VERSION 5.7 ;
  NOWIREEXTENSIONATPIN ON ;
  DIVIDERCHAR "/" ;
  BUSBITCHARS "[]" ;
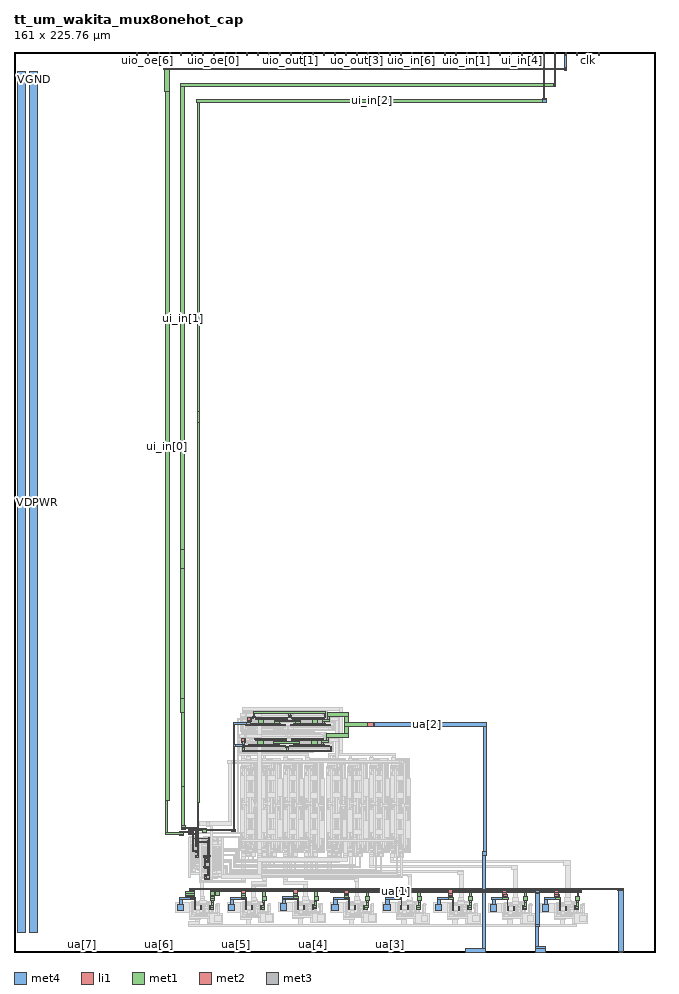
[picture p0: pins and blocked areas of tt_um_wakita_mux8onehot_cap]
MACRO tt_um_wakita_mux8onehot_cap
  CLASS BLOCK ;
  FOREIGN tt_um_wakita_mux8onehot_cap ;
  ORIGIN 0.000 0.000 ;
  SIZE 161.000 BY 225.760 ;
  PIN clk
    DIRECTION INPUT ;
    USE SIGNAL ;
    PORT
      LAYER met4 ;
        RECT 143.830 224.760 144.130 225.760 ;
    END
  END clk
  PIN ena
    DIRECTION INPUT ;
    USE SIGNAL ;
    PORT
      LAYER met4 ;
        RECT 146.590 224.760 146.890 225.760 ;
    END
  END ena
  PIN rst_n
    DIRECTION INPUT ;
    USE SIGNAL ;
    PORT
      LAYER met4 ;
        RECT 141.070 224.760 141.370 225.760 ;
    END
  END rst_n
  PIN ua[0]
    DIRECTION INOUT ;
    USE SIGNAL ;
    ANTENNAGATEAREA 8.000000 ;
    PORT
      LAYER li1 ;
        RECT 45.270 10.600 45.440 11.600 ;
        RECT 46.820 10.600 46.990 11.600 ;
        RECT 58.120 10.620 58.290 11.620 ;
        RECT 59.670 10.620 59.840 11.620 ;
        RECT 71.130 10.690 71.300 11.690 ;
        RECT 72.680 10.690 72.850 11.690 ;
        RECT 83.980 10.620 84.150 11.620 ;
        RECT 85.530 10.620 85.700 11.620 ;
        RECT 97.100 10.570 97.270 11.570 ;
        RECT 98.650 10.570 98.820 11.570 ;
        RECT 110.000 10.520 110.170 11.520 ;
        RECT 111.550 10.520 111.720 11.520 ;
        RECT 123.740 10.480 123.910 11.480 ;
        RECT 125.290 10.480 125.460 11.480 ;
        RECT 136.830 10.480 137.000 11.480 ;
        RECT 138.380 10.480 138.550 11.480 ;
      LAYER met1 ;
        RECT 44.120 15.280 45.120 15.450 ;
        RECT 42.930 15.120 45.120 15.280 ;
        RECT 42.930 14.560 45.200 15.120 ;
        RECT 42.930 14.090 45.230 14.560 ;
        RECT 57.000 14.190 58.100 14.640 ;
        RECT 70.020 14.290 71.120 14.740 ;
        RECT 82.790 14.390 83.890 14.650 ;
        RECT 42.930 13.920 45.190 14.090 ;
        RECT 44.190 13.710 45.190 13.920 ;
        RECT 57.040 13.730 58.040 14.190 ;
        RECT 70.050 13.800 71.050 14.290 ;
        RECT 82.790 14.200 83.900 14.390 ;
        RECT 44.190 13.370 45.460 13.710 ;
        RECT 57.040 13.390 58.310 13.730 ;
        RECT 70.050 13.460 71.320 13.800 ;
        RECT 44.510 13.220 45.460 13.370 ;
        RECT 57.360 13.240 58.310 13.390 ;
        RECT 70.370 13.310 71.320 13.460 ;
        RECT 82.900 13.730 83.900 14.200 ;
        RECT 95.950 14.140 97.050 14.590 ;
        RECT 82.900 13.390 84.170 13.730 ;
        RECT 45.280 11.580 45.420 13.220 ;
        RECT 58.130 11.600 58.270 13.240 ;
        RECT 71.140 11.670 71.280 13.310 ;
        RECT 83.220 13.240 84.170 13.390 ;
        RECT 96.020 13.680 97.020 14.140 ;
        RECT 108.890 14.050 109.990 14.500 ;
        RECT 96.020 13.340 97.290 13.680 ;
        RECT 45.240 10.620 45.470 11.580 ;
        RECT 46.790 10.620 47.020 11.580 ;
        RECT 58.090 10.640 58.320 11.600 ;
        RECT 59.640 10.640 59.870 11.600 ;
        RECT 71.100 10.710 71.330 11.670 ;
        RECT 72.650 10.710 72.880 11.670 ;
        RECT 83.990 11.600 84.130 13.240 ;
        RECT 96.340 13.190 97.290 13.340 ;
        RECT 108.920 13.630 109.920 14.050 ;
        RECT 122.620 14.040 123.720 14.490 ;
        RECT 135.650 14.040 136.750 14.490 ;
        RECT 108.920 13.290 110.190 13.630 ;
        RECT 83.950 10.640 84.180 11.600 ;
        RECT 85.500 10.640 85.730 11.600 ;
        RECT 97.110 11.550 97.250 13.190 ;
        RECT 109.240 13.140 110.190 13.290 ;
        RECT 122.660 13.590 123.660 14.040 ;
        RECT 135.750 13.590 136.750 14.040 ;
        RECT 122.660 13.250 123.930 13.590 ;
        RECT 135.750 13.250 137.020 13.590 ;
        RECT 97.070 10.590 97.300 11.550 ;
        RECT 98.620 10.590 98.850 11.550 ;
        RECT 110.010 11.500 110.150 13.140 ;
        RECT 122.980 13.100 123.930 13.250 ;
        RECT 136.070 13.100 137.020 13.250 ;
        RECT 109.970 10.540 110.200 11.500 ;
        RECT 111.520 10.540 111.750 11.500 ;
        RECT 123.750 11.460 123.890 13.100 ;
        RECT 136.840 11.460 136.980 13.100 ;
        RECT 123.710 10.500 123.940 11.460 ;
        RECT 125.260 10.500 125.490 11.460 ;
        RECT 136.800 10.500 137.030 11.460 ;
        RECT 138.350 10.500 138.580 11.460 ;
      LAYER met2 ;
        RECT 44.160 15.920 45.180 15.930 ;
        RECT 44.120 15.890 65.770 15.920 ;
        RECT 70.070 15.890 71.040 15.950 ;
        RECT 151.510 15.910 152.780 15.970 ;
        RECT 86.560 15.890 108.210 15.900 ;
        RECT 138.420 15.890 152.780 15.910 ;
        RECT 44.120 15.650 152.780 15.890 ;
        RECT 44.160 13.900 45.180 15.650 ;
        RECT 57.080 14.690 58.050 15.650 ;
        RECT 65.380 15.640 152.780 15.650 ;
        RECT 65.380 15.630 139.680 15.640 ;
        RECT 65.380 15.620 87.030 15.630 ;
        RECT 57.050 14.140 58.050 14.690 ;
        RECT 70.070 14.790 71.040 15.620 ;
        RECT 70.070 14.240 71.070 14.790 ;
        RECT 82.880 14.700 83.850 15.620 ;
        RECT 82.840 14.450 83.850 14.700 ;
        RECT 95.990 14.640 96.960 15.630 ;
        RECT 107.780 15.620 129.430 15.630 ;
        RECT 82.840 14.150 83.840 14.450 ;
        RECT 95.990 14.420 97.000 14.640 ;
        RECT 96.000 14.090 97.000 14.420 ;
        RECT 108.930 14.550 109.900 15.620 ;
        RECT 108.930 14.230 109.940 14.550 ;
        RECT 122.660 14.540 123.630 15.620 ;
        RECT 135.670 14.540 136.640 15.630 ;
        RECT 151.510 15.340 152.780 15.640 ;
        RECT 122.660 14.370 123.670 14.540 ;
        RECT 135.670 14.370 136.700 14.540 ;
        RECT 108.940 14.000 109.940 14.230 ;
        RECT 122.670 13.990 123.670 14.370 ;
        RECT 135.700 13.990 136.700 14.370 ;
        RECT 44.560 13.170 45.410 13.760 ;
        RECT 57.410 13.190 58.260 13.780 ;
        RECT 70.420 13.260 71.270 13.850 ;
        RECT 83.270 13.190 84.120 13.780 ;
        RECT 96.390 13.140 97.240 13.730 ;
        RECT 109.290 13.090 110.140 13.680 ;
        RECT 123.030 13.050 123.880 13.640 ;
        RECT 136.120 13.050 136.970 13.640 ;
      LAYER met3 ;
        RECT 151.460 15.365 152.830 15.945 ;
        RECT 44.510 13.195 45.460 13.735 ;
        RECT 57.360 13.215 58.310 13.755 ;
        RECT 70.370 13.285 71.320 13.825 ;
        RECT 83.220 13.215 84.170 13.755 ;
        RECT 96.340 13.165 97.290 13.705 ;
        RECT 109.240 13.115 110.190 13.655 ;
        RECT 122.980 13.075 123.930 13.615 ;
        RECT 136.070 13.075 137.020 13.615 ;
      LAYER met4 ;
        RECT 151.505 15.900 152.785 15.925 ;
        RECT 151.505 15.385 152.800 15.900 ;
        RECT 70.415 13.800 71.275 13.805 ;
        RECT 57.405 13.730 58.265 13.735 ;
        RECT 44.555 13.710 45.415 13.715 ;
        RECT 41.400 13.215 45.415 13.710 ;
        RECT 54.250 13.235 58.265 13.730 ;
        RECT 67.260 13.305 71.275 13.800 ;
        RECT 83.265 13.730 84.125 13.735 ;
        RECT 67.260 13.270 71.240 13.305 ;
        RECT 41.400 13.180 45.380 13.215 ;
        RECT 54.250 13.200 58.230 13.235 ;
        RECT 41.440 12.005 42.320 13.180 ;
        RECT 54.290 12.025 55.170 13.200 ;
        RECT 67.300 12.095 68.180 13.270 ;
        RECT 80.110 13.235 84.125 13.730 ;
        RECT 96.385 13.680 97.245 13.685 ;
        RECT 80.110 13.200 84.090 13.235 ;
        RECT 40.975 10.395 42.585 12.005 ;
        RECT 53.825 10.415 55.435 12.025 ;
        RECT 66.835 10.485 68.445 12.095 ;
        RECT 80.150 12.025 81.030 13.200 ;
        RECT 93.230 13.185 97.245 13.680 ;
        RECT 109.285 13.630 110.145 13.635 ;
        RECT 93.230 13.150 97.210 13.185 ;
        RECT 79.685 10.415 81.295 12.025 ;
        RECT 93.270 11.975 94.150 13.150 ;
        RECT 106.130 13.135 110.145 13.630 ;
        RECT 123.025 13.590 123.885 13.595 ;
        RECT 136.115 13.590 136.975 13.595 ;
        RECT 106.130 13.100 110.110 13.135 ;
        RECT 92.805 10.365 94.415 11.975 ;
        RECT 106.170 11.925 107.050 13.100 ;
        RECT 119.870 13.095 123.885 13.590 ;
        RECT 132.960 13.095 136.975 13.590 ;
        RECT 119.870 13.060 123.850 13.095 ;
        RECT 132.960 13.060 136.940 13.095 ;
        RECT 105.705 10.315 107.315 11.925 ;
        RECT 119.910 11.885 120.790 13.060 ;
        RECT 133.000 11.885 133.880 13.060 ;
        RECT 119.445 10.275 121.055 11.885 ;
        RECT 132.535 10.275 134.145 11.885 ;
        RECT 151.620 0.200 152.800 15.385 ;
        RECT 151.810 0.000 152.710 0.200 ;
    END
  END ua[0]
  PIN ua[1]
    DIRECTION INOUT ;
    USE SIGNAL ;
    ANTENNADIFFAREA 2.320000 ;
    PORT
      LAYER li1 ;
        RECT 49.040 10.660 49.210 11.700 ;
        RECT 61.890 10.680 62.060 11.720 ;
        RECT 74.900 10.750 75.070 11.790 ;
        RECT 87.750 10.680 87.920 11.720 ;
        RECT 100.870 10.630 101.040 11.670 ;
        RECT 113.770 10.580 113.940 11.620 ;
        RECT 127.510 10.540 127.680 11.580 ;
        RECT 140.600 10.540 140.770 11.580 ;
      LAYER met1 ;
        RECT 49.380 15.340 50.360 15.370 ;
        RECT 49.380 15.320 63.180 15.340 ;
        RECT 79.430 15.320 97.290 15.340 ;
        RECT 130.790 15.330 131.720 15.350 ;
        RECT 114.490 15.320 142.240 15.330 ;
        RECT 49.380 15.130 142.240 15.320 ;
        RECT 49.370 15.090 142.240 15.130 ;
        RECT 49.370 14.130 50.370 15.090 ;
        RECT 50.580 14.240 51.580 15.090 ;
        RECT 62.440 15.070 142.240 15.090 ;
        RECT 49.380 13.950 50.360 14.130 ;
        RECT 62.440 13.970 63.050 15.070 ;
        RECT 75.440 14.040 76.050 15.070 ;
        RECT 79.430 15.050 142.240 15.070 ;
        RECT 49.380 13.430 50.400 13.950 ;
        RECT 49.400 12.950 50.400 13.430 ;
        RECT 62.250 12.970 63.250 13.970 ;
        RECT 75.260 13.040 76.260 14.040 ;
        RECT 88.320 13.970 88.930 15.050 ;
        RECT 49.590 12.460 50.090 12.950 ;
        RECT 62.440 12.480 62.940 12.970 ;
        RECT 75.450 12.550 75.950 13.040 ;
        RECT 88.110 12.970 89.110 13.970 ;
        RECT 101.300 13.920 101.910 15.050 ;
        RECT 114.240 15.030 142.240 15.050 ;
        RECT 49.010 11.620 49.240 11.680 ;
        RECT 49.620 11.620 50.090 12.460 ;
        RECT 49.010 11.130 50.090 11.620 ;
        RECT 61.860 11.640 62.090 11.700 ;
        RECT 62.470 11.640 62.940 12.480 ;
        RECT 61.860 11.150 62.940 11.640 ;
        RECT 74.870 11.710 75.100 11.770 ;
        RECT 75.480 11.710 75.950 12.550 ;
        RECT 88.300 12.480 88.800 12.970 ;
        RECT 101.230 12.920 102.230 13.920 ;
        RECT 114.240 13.870 114.850 15.030 ;
        RECT 74.870 11.220 75.950 11.710 ;
        RECT 87.720 11.640 87.950 11.700 ;
        RECT 88.330 11.640 88.800 12.480 ;
        RECT 101.420 12.430 101.920 12.920 ;
        RECT 114.130 12.870 115.130 13.870 ;
        RECT 127.980 13.830 128.590 15.030 ;
        RECT 141.270 13.830 141.690 15.030 ;
        RECT 49.010 10.760 50.070 11.130 ;
        RECT 61.860 10.780 62.920 11.150 ;
        RECT 74.870 10.850 75.930 11.220 ;
        RECT 87.720 11.150 88.800 11.640 ;
        RECT 100.840 11.590 101.070 11.650 ;
        RECT 101.450 11.590 101.920 12.430 ;
        RECT 114.320 12.380 114.820 12.870 ;
        RECT 127.870 12.830 128.870 13.830 ;
        RECT 140.960 12.830 141.960 13.830 ;
        RECT 49.010 10.680 49.240 10.760 ;
        RECT 61.860 10.700 62.090 10.780 ;
        RECT 74.870 10.770 75.100 10.850 ;
        RECT 87.720 10.780 88.780 11.150 ;
        RECT 100.840 11.100 101.920 11.590 ;
        RECT 113.740 11.540 113.970 11.600 ;
        RECT 114.350 11.540 114.820 12.380 ;
        RECT 128.060 12.340 128.560 12.830 ;
        RECT 141.150 12.340 141.650 12.830 ;
        RECT 87.720 10.700 87.950 10.780 ;
        RECT 100.840 10.730 101.900 11.100 ;
        RECT 113.740 11.050 114.820 11.540 ;
        RECT 127.480 11.500 127.710 11.560 ;
        RECT 128.090 11.500 128.560 12.340 ;
        RECT 100.840 10.650 101.070 10.730 ;
        RECT 113.740 10.680 114.800 11.050 ;
        RECT 127.480 11.010 128.560 11.500 ;
        RECT 140.570 11.500 140.800 11.560 ;
        RECT 141.180 11.500 141.650 12.340 ;
        RECT 140.570 11.010 141.650 11.500 ;
        RECT 113.740 10.600 113.970 10.680 ;
        RECT 127.480 10.640 128.540 11.010 ;
        RECT 140.570 10.640 141.630 11.010 ;
        RECT 127.480 10.560 127.710 10.640 ;
        RECT 140.570 10.560 140.800 10.640 ;
      LAYER met2 ;
        RECT 130.840 14.980 131.670 15.400 ;
      LAYER met3 ;
        RECT 130.790 15.005 131.720 15.375 ;
      LAYER met4 ;
        RECT 130.840 15.355 131.700 15.380 ;
        RECT 130.835 15.025 131.700 15.355 ;
        RECT 130.840 14.760 131.700 15.025 ;
        RECT 130.910 6.800 131.700 14.760 ;
        RECT 130.890 6.510 131.700 6.800 ;
        RECT 130.890 1.380 131.690 6.510 ;
        RECT 130.880 1.000 133.380 1.380 ;
        RECT 130.880 0.000 133.390 1.000 ;
        RECT 130.880 -0.030 133.380 0.000 ;
    END
  END ua[1]
  PIN ua[2]
    DIRECTION INOUT ;
    USE SIGNAL ;
    ANTENNADIFFAREA 20.879999 ;
    PORT
      LAYER li1 ;
        RECT 60.595 58.615 68.635 58.785 ;
        RECT 69.685 58.615 77.725 58.785 ;
        RECT 58.130 56.935 68.170 57.105 ;
        RECT 69.310 56.935 79.350 57.105 ;
        RECT 60.405 53.325 68.445 53.495 ;
        RECT 69.495 53.325 77.535 53.495 ;
        RECT 57.940 51.645 67.980 51.815 ;
        RECT 69.120 51.645 79.160 51.815 ;
      LAYER met1 ;
        RECT 78.855 60.125 83.915 60.175 ;
        RECT 78.665 59.175 83.915 60.125 ;
        RECT 78.665 59.125 79.925 59.175 ;
        RECT 60.615 58.585 68.615 58.815 ;
        RECT 69.705 58.665 77.705 58.815 ;
        RECT 69.705 58.585 77.945 58.665 ;
        RECT 60.695 58.315 68.605 58.585 ;
        RECT 69.755 58.385 77.945 58.585 ;
        RECT 78.665 58.385 79.195 59.125 ;
        RECT 61.385 57.405 62.685 58.315 ;
        RECT 65.315 58.105 66.615 58.315 ;
        RECT 69.755 58.305 79.195 58.385 ;
        RECT 70.575 58.105 71.875 58.305 ;
        RECT 65.315 57.695 71.875 58.105 ;
        RECT 65.315 57.405 66.615 57.695 ;
        RECT 58.965 57.135 66.875 57.405 ;
        RECT 70.575 57.375 71.875 57.695 ;
        RECT 74.915 57.375 76.215 58.305 ;
        RECT 77.365 57.915 79.195 58.305 ;
        RECT 77.365 57.375 77.945 57.915 ;
        RECT 82.915 57.580 83.915 59.175 ;
        RECT 85.400 57.590 90.120 57.610 ;
        RECT 85.280 57.580 90.120 57.590 ;
        RECT 70.225 57.135 78.135 57.375 ;
        RECT 58.150 56.905 68.150 57.135 ;
        RECT 69.330 56.905 79.330 57.135 ;
        RECT 82.915 56.600 90.120 57.580 ;
        RECT 82.915 54.835 83.915 56.600 ;
        RECT 85.280 56.590 86.280 56.600 ;
        RECT 78.475 53.835 83.915 54.835 ;
        RECT 60.425 53.295 68.425 53.525 ;
        RECT 69.515 53.375 77.515 53.525 ;
        RECT 69.515 53.295 77.755 53.375 ;
        RECT 60.505 53.025 68.415 53.295 ;
        RECT 69.565 53.095 77.755 53.295 ;
        RECT 78.475 53.095 79.005 53.835 ;
        RECT 61.195 52.115 62.495 53.025 ;
        RECT 65.125 52.815 66.425 53.025 ;
        RECT 69.565 53.015 79.005 53.095 ;
        RECT 70.385 52.815 71.685 53.015 ;
        RECT 65.125 52.405 71.685 52.815 ;
        RECT 65.125 52.115 66.425 52.405 ;
        RECT 58.775 51.845 66.685 52.115 ;
        RECT 70.385 52.085 71.685 52.405 ;
        RECT 74.725 52.085 76.025 53.015 ;
        RECT 77.175 52.625 79.005 53.015 ;
        RECT 77.175 52.085 77.755 52.625 ;
        RECT 70.035 51.845 77.945 52.085 ;
        RECT 57.960 51.615 67.960 51.845 ;
        RECT 69.140 51.615 79.140 51.845 ;
      LAYER met2 ;
        RECT 88.780 56.600 90.060 57.640 ;
      LAYER met3 ;
        RECT 88.730 57.570 90.110 57.615 ;
        RECT 88.610 56.650 90.370 57.570 ;
        RECT 88.730 56.625 90.110 56.650 ;
      LAYER met4 ;
        RECT 88.730 57.575 118.340 57.610 ;
        RECT 88.655 57.460 118.340 57.575 ;
        RECT 88.655 56.645 118.400 57.460 ;
        RECT 88.730 56.600 118.400 56.645 ;
        RECT 117.680 25.230 118.400 56.600 ;
        RECT 117.560 24.260 118.400 25.230 ;
        RECT 113.170 0.950 114.070 1.000 ;
        RECT 117.560 0.950 118.380 24.260 ;
        RECT 113.170 0.000 118.380 0.950 ;
        RECT 113.360 -0.010 118.380 0.000 ;
    END
  END ua[2]
  PIN ua[3]
    DIRECTION INOUT ;
    USE SIGNAL ;
    PORT
      LAYER met4 ;
        RECT 93.850 0.000 94.750 1.000 ;
    END
  END ua[3]
  PIN ua[4]
    DIRECTION INOUT ;
    USE SIGNAL ;
    PORT
      LAYER met4 ;
        RECT 74.530 0.000 75.430 1.000 ;
    END
  END ua[4]
  PIN ua[5]
    DIRECTION INOUT ;
    USE SIGNAL ;
    PORT
      LAYER met4 ;
        RECT 55.210 0.000 56.110 1.000 ;
    END
  END ua[5]
  PIN ua[6]
    DIRECTION INOUT ;
    USE SIGNAL ;
    PORT
      LAYER met4 ;
        RECT 35.890 0.000 36.790 1.000 ;
    END
  END ua[6]
  PIN ua[7]
    DIRECTION INOUT ;
    USE SIGNAL ;
    PORT
      LAYER met4 ;
        RECT 16.570 0.000 17.470 1.000 ;
    END
  END ua[7]
  PIN ui_in[0]
    DIRECTION INPUT ;
    USE SIGNAL ;
    ANTENNAGATEAREA 0.873000 ;
    PORT
      LAYER li1 ;
        RECT 45.500 25.120 45.750 25.450 ;
        RECT 47.590 23.860 48.440 24.160 ;
        RECT 48.470 22.435 48.780 23.130 ;
        RECT 47.900 18.915 48.150 18.970 ;
        RECT 47.900 18.560 48.225 18.915 ;
        RECT 47.900 18.295 48.510 18.560 ;
      LAYER met1 ;
        RECT 138.160 221.670 138.610 221.750 ;
        RECT 37.510 221.250 138.610 221.670 ;
        RECT 37.750 215.770 39.000 221.250 ;
        RECT 138.160 221.190 138.610 221.250 ;
        RECT 37.950 38.080 38.980 215.770 ;
        RECT 38.010 29.940 38.530 38.080 ;
        RECT 41.500 30.210 42.500 30.280 ;
        RECT 41.500 29.940 45.145 30.210 ;
        RECT 38.010 29.880 45.145 29.940 ;
        RECT 38.010 29.540 42.500 29.880 ;
        RECT 41.500 29.280 42.500 29.540 ;
        RECT 44.815 28.395 45.145 29.880 ;
        RECT 44.805 28.045 45.145 28.395 ;
        RECT 48.835 28.555 49.105 28.645 ;
        RECT 48.835 28.265 49.115 28.555 ;
        RECT 44.815 25.460 45.145 28.045 ;
        RECT 45.475 25.460 45.775 25.505 ;
        RECT 44.815 25.130 45.775 25.460 ;
        RECT 45.475 25.075 45.775 25.130 ;
        RECT 47.525 24.165 48.225 24.185 ;
        RECT 47.525 23.845 48.265 24.165 ;
        RECT 48.945 24.155 49.115 28.265 ;
        RECT 47.525 23.825 48.225 23.845 ;
        RECT 48.900 23.835 49.160 24.155 ;
        RECT 48.475 23.105 48.755 23.125 ;
        RECT 48.455 22.995 48.755 23.105 ;
        RECT 48.355 22.925 48.755 22.995 ;
        RECT 48.945 22.925 49.115 23.835 ;
        RECT 48.355 22.615 49.160 22.925 ;
        RECT 48.355 22.555 48.755 22.615 ;
        RECT 48.900 22.605 49.160 22.615 ;
        RECT 48.455 22.445 48.755 22.555 ;
        RECT 48.475 22.435 48.755 22.445 ;
        RECT 47.910 18.975 48.160 18.980 ;
        RECT 47.875 18.560 48.255 18.975 ;
        RECT 48.945 18.560 49.115 22.605 ;
        RECT 47.875 18.350 49.115 18.560 ;
        RECT 47.875 18.310 49.040 18.350 ;
        RECT 47.875 18.245 48.255 18.310 ;
      LAYER met2 ;
        RECT 138.210 221.140 138.560 221.800 ;
        RECT 43.970 30.210 44.300 30.240 ;
        RECT 43.660 29.880 44.300 30.210 ;
        RECT 43.970 29.850 44.300 29.880 ;
        RECT 44.815 28.565 45.135 28.600 ;
        RECT 48.785 28.565 49.155 28.595 ;
        RECT 44.815 28.370 49.155 28.565 ;
        RECT 44.815 28.340 45.135 28.370 ;
        RECT 48.785 28.315 49.155 28.370 ;
        RECT 47.495 24.080 47.815 24.125 ;
        RECT 48.870 24.080 49.190 24.125 ;
        RECT 47.495 23.910 49.190 24.080 ;
        RECT 47.495 23.865 47.815 23.910 ;
        RECT 48.870 23.865 49.190 23.910 ;
      LAYER met3 ;
        RECT 138.160 221.165 138.610 221.775 ;
      LAYER met4 ;
        RECT 138.310 225.170 138.610 225.760 ;
        RECT 138.210 224.760 138.610 225.170 ;
        RECT 138.210 221.755 138.540 224.760 ;
        RECT 138.205 221.185 138.565 221.755 ;
    END
  END ui_in[0]
  PIN ui_in[1]
    DIRECTION INPUT ;
    USE SIGNAL ;
    ANTENNAGATEAREA 0.873000 ;
    PORT
      LAYER li1 ;
        RECT 45.515 26.830 45.735 26.835 ;
        RECT 45.500 26.500 45.750 26.830 ;
        RECT 48.470 25.195 48.780 25.890 ;
        RECT 47.590 21.100 48.440 21.400 ;
        RECT 47.900 19.190 48.150 19.530 ;
      LAYER met1 ;
        RECT 41.870 217.800 42.790 217.950 ;
        RECT 135.480 217.800 135.870 217.810 ;
        RECT 41.740 217.130 135.870 217.800 ;
        RECT 41.870 100.850 42.790 217.130 ;
        RECT 41.840 96.160 42.790 100.850 ;
        RECT 41.840 63.550 42.750 96.160 ;
        RECT 41.840 60.070 42.830 63.550 ;
        RECT 41.910 41.410 42.830 60.070 ;
        RECT 41.960 31.660 42.800 41.410 ;
        RECT 41.920 31.320 42.920 31.660 ;
        RECT 41.920 30.940 45.840 31.320 ;
        RECT 41.920 30.660 42.920 30.940 ;
        RECT 45.480 29.730 45.820 30.940 ;
        RECT 45.465 29.580 45.820 29.730 ;
        RECT 45.465 26.475 45.795 29.580 ;
        RECT 48.475 27.375 48.795 27.875 ;
        RECT 45.485 26.455 45.765 26.475 ;
        RECT 48.475 25.875 48.745 27.375 ;
        RECT 48.445 25.865 48.745 25.875 ;
        RECT 48.445 25.205 48.785 25.865 ;
        RECT 48.475 25.195 48.785 25.205 ;
        RECT 48.475 23.705 48.745 25.195 ;
        RECT 47.845 23.355 48.105 23.675 ;
        RECT 47.870 21.425 48.080 23.355 ;
        RECT 48.475 23.345 48.795 23.705 ;
        RECT 48.435 21.425 48.695 21.445 ;
        RECT 47.665 21.405 48.695 21.425 ;
        RECT 47.645 21.085 48.695 21.405 ;
        RECT 47.665 21.045 48.695 21.085 ;
        RECT 47.895 19.555 48.165 19.565 ;
        RECT 47.885 19.545 48.165 19.555 ;
        RECT 48.435 19.545 48.695 21.045 ;
        RECT 47.885 19.225 48.695 19.545 ;
        RECT 47.885 19.165 48.165 19.225 ;
        RECT 48.435 19.195 48.695 19.225 ;
      LAYER met2 ;
        RECT 135.530 217.080 135.820 217.860 ;
        RECT 43.680 29.370 45.825 29.700 ;
        RECT 45.445 27.745 45.885 27.905 ;
        RECT 48.425 27.745 48.865 27.825 ;
        RECT 45.445 27.505 48.865 27.745 ;
        RECT 47.815 23.620 48.135 23.645 ;
        RECT 48.505 23.620 48.765 23.675 ;
        RECT 47.815 23.410 48.765 23.620 ;
        RECT 47.815 23.385 48.135 23.410 ;
        RECT 48.505 23.355 48.765 23.410 ;
      LAYER met3 ;
        RECT 135.440 217.070 135.900 217.850 ;
      LAYER met4 ;
        RECT 135.550 225.310 135.850 225.760 ;
        RECT 135.520 224.760 135.850 225.310 ;
        RECT 135.520 217.855 135.820 224.760 ;
        RECT 135.485 217.065 135.855 217.855 ;
    END
  END ui_in[1]
  PIN ui_in[2]
    DIRECTION INPUT ;
    USE SIGNAL ;
    ANTENNAGATEAREA 13.094999 ;
    PORT
      LAYER li1 ;
        RECT 60.255 58.845 60.425 59.195 ;
        RECT 68.805 58.845 68.975 59.195 ;
        RECT 69.345 58.845 69.515 59.195 ;
        RECT 77.895 58.845 78.065 59.195 ;
        RECT 57.555 51.235 57.725 51.585 ;
        RECT 68.195 51.235 68.365 51.585 ;
        RECT 68.735 51.235 68.905 51.585 ;
        RECT 79.375 51.235 79.545 51.585 ;
        RECT 45.505 24.070 45.745 24.085 ;
        RECT 45.500 23.740 45.750 24.070 ;
      LAYER met1 ;
        RECT 45.970 213.770 46.490 213.790 ;
        RECT 132.490 213.770 133.510 214.060 ;
        RECT 45.850 213.210 133.510 213.770 ;
        RECT 45.970 135.630 46.490 213.210 ;
        RECT 132.490 213.140 133.510 213.210 ;
        RECT 45.950 132.930 46.490 135.630 ;
        RECT 45.950 37.620 46.450 132.930 ;
        RECT 60.145 59.875 78.175 60.235 ;
        RECT 60.145 59.175 60.425 59.875 ;
        RECT 68.845 59.235 69.445 59.875 ;
        RECT 68.775 59.175 69.515 59.235 ;
        RECT 60.145 59.165 60.455 59.175 ;
        RECT 59.745 58.935 60.455 59.165 ;
        RECT 58.475 58.865 60.455 58.935 ;
        RECT 68.775 58.865 69.545 59.175 ;
        RECT 58.475 58.475 59.995 58.865 ;
        RECT 68.775 58.835 69.515 58.865 ;
        RECT 77.865 58.845 78.165 59.875 ;
        RECT 58.475 57.935 59.475 58.475 ;
        RECT 57.055 52.645 58.055 53.645 ;
        RECT 57.415 50.455 57.785 52.645 ;
        RECT 68.185 51.565 68.915 51.585 ;
        RECT 79.355 51.565 79.625 51.595 ;
        RECT 68.165 51.255 68.935 51.565 ;
        RECT 79.345 51.255 79.625 51.565 ;
        RECT 68.335 50.455 68.785 51.255 ;
        RECT 79.355 50.455 79.625 51.255 ;
        RECT 57.415 50.185 79.625 50.455 ;
        RECT 45.970 33.380 46.260 37.620 ;
        RECT 45.970 32.830 46.280 33.380 ;
        RECT 45.990 31.070 46.280 32.830 ;
        RECT 46.460 31.090 47.680 31.100 ;
        RECT 46.460 31.070 48.250 31.090 ;
        RECT 45.990 30.940 48.250 31.070 ;
        RECT 46.050 30.740 48.250 30.940 ;
        RECT 46.035 30.640 48.250 30.740 ;
        RECT 45.475 24.110 45.775 24.145 ;
        RECT 46.035 24.110 46.365 30.640 ;
        RECT 47.250 30.090 48.250 30.640 ;
        RECT 45.475 23.780 46.365 24.110 ;
        RECT 45.475 23.695 45.775 23.780 ;
      LAYER met2 ;
        RECT 132.540 213.090 133.460 214.110 ;
        RECT 58.625 58.125 59.355 58.815 ;
        RECT 57.165 52.705 57.935 53.575 ;
        RECT 54.635 30.710 55.480 30.785 ;
        RECT 43.670 30.380 55.480 30.710 ;
        RECT 54.635 30.305 55.480 30.380 ;
      LAYER met3 ;
        RECT 132.490 213.115 133.510 214.085 ;
        RECT 58.775 57.660 59.335 58.705 ;
        RECT 58.430 57.635 59.335 57.660 ;
        RECT 54.975 52.065 55.420 57.615 ;
        RECT 58.425 57.075 59.335 57.635 ;
        RECT 58.430 57.050 58.980 57.075 ;
        RECT 57.115 52.730 57.985 53.550 ;
        RECT 54.975 51.505 55.485 52.065 ;
        RECT 57.235 51.755 57.825 52.730 ;
        RECT 54.975 30.810 55.420 51.505 ;
        RECT 57.275 51.500 57.785 51.755 ;
        RECT 54.930 30.280 55.460 30.810 ;
      LAYER met4 ;
        RECT 132.790 225.340 133.090 225.760 ;
        RECT 132.770 214.065 133.150 225.340 ;
        RECT 132.535 213.135 133.465 214.065 ;
        RECT 132.770 213.100 133.150 213.135 ;
        RECT 54.970 57.580 55.425 57.590 ;
        RECT 58.425 57.580 59.300 57.635 ;
        RECT 54.970 57.135 59.300 57.580 ;
        RECT 58.425 57.075 59.300 57.135 ;
        RECT 57.270 52.040 57.790 52.045 ;
        RECT 54.980 51.530 57.790 52.040 ;
        RECT 57.270 51.525 57.790 51.530 ;
    END
  END ui_in[2]
  PIN ui_in[3]
    DIRECTION INPUT ;
    USE SIGNAL ;
    PORT
      LAYER met4 ;
        RECT 130.030 224.760 130.330 225.760 ;
    END
  END ui_in[3]
  PIN ui_in[4]
    DIRECTION INPUT ;
    USE SIGNAL ;
    PORT
      LAYER met4 ;
        RECT 127.270 224.760 127.570 225.760 ;
    END
  END ui_in[4]
  PIN ui_in[5]
    DIRECTION INPUT ;
    USE SIGNAL ;
    PORT
      LAYER met4 ;
        RECT 124.510 224.760 124.810 225.760 ;
    END
  END ui_in[5]
  PIN ui_in[6]
    DIRECTION INPUT ;
    USE SIGNAL ;
    PORT
      LAYER met4 ;
        RECT 121.750 224.760 122.050 225.760 ;
    END
  END ui_in[6]
  PIN ui_in[7]
    DIRECTION INPUT ;
    USE SIGNAL ;
    PORT
      LAYER met4 ;
        RECT 118.990 224.760 119.290 225.760 ;
    END
  END ui_in[7]
  PIN uio_in[0]
    DIRECTION INPUT ;
    USE SIGNAL ;
    PORT
      LAYER met4 ;
        RECT 116.230 224.760 116.530 225.760 ;
    END
  END uio_in[0]
  PIN uio_in[1]
    DIRECTION INPUT ;
    USE SIGNAL ;
    PORT
      LAYER met4 ;
        RECT 113.470 224.760 113.770 225.760 ;
    END
  END uio_in[1]
  PIN uio_in[2]
    DIRECTION INPUT ;
    USE SIGNAL ;
    PORT
      LAYER met4 ;
        RECT 110.710 224.760 111.010 225.760 ;
    END
  END uio_in[2]
  PIN uio_in[3]
    DIRECTION INPUT ;
    USE SIGNAL ;
    PORT
      LAYER met4 ;
        RECT 107.950 224.760 108.250 225.760 ;
    END
  END uio_in[3]
  PIN uio_in[4]
    DIRECTION INPUT ;
    USE SIGNAL ;
    PORT
      LAYER met4 ;
        RECT 105.190 224.760 105.490 225.760 ;
    END
  END uio_in[4]
  PIN uio_in[5]
    DIRECTION INPUT ;
    USE SIGNAL ;
    PORT
      LAYER met4 ;
        RECT 102.430 224.760 102.730 225.760 ;
    END
  END uio_in[5]
  PIN uio_in[6]
    DIRECTION INPUT ;
    USE SIGNAL ;
    PORT
      LAYER met4 ;
        RECT 99.670 224.760 99.970 225.760 ;
    END
  END uio_in[6]
  PIN uio_in[7]
    DIRECTION INPUT ;
    USE SIGNAL ;
    PORT
      LAYER met4 ;
        RECT 96.910 224.760 97.210 225.760 ;
    END
  END uio_in[7]
  PIN uio_oe[0]
    DIRECTION OUTPUT ;
    USE SIGNAL ;
    PORT
      LAYER met4 ;
        RECT 49.990 224.760 50.290 225.760 ;
    END
  END uio_oe[0]
  PIN uio_oe[1]
    DIRECTION OUTPUT ;
    USE SIGNAL ;
    PORT
      LAYER met4 ;
        RECT 47.230 224.760 47.530 225.760 ;
    END
  END uio_oe[1]
  PIN uio_oe[2]
    DIRECTION OUTPUT ;
    USE SIGNAL ;
    PORT
      LAYER met4 ;
        RECT 44.470 224.760 44.770 225.760 ;
    END
  END uio_oe[2]
  PIN uio_oe[3]
    DIRECTION OUTPUT ;
    USE SIGNAL ;
    PORT
      LAYER met4 ;
        RECT 41.710 224.760 42.010 225.760 ;
    END
  END uio_oe[3]
  PIN uio_oe[4]
    DIRECTION OUTPUT ;
    USE SIGNAL ;
    PORT
      LAYER met4 ;
        RECT 38.950 224.760 39.250 225.760 ;
    END
  END uio_oe[4]
  PIN uio_oe[5]
    DIRECTION OUTPUT ;
    USE SIGNAL ;
    PORT
      LAYER met4 ;
        RECT 36.190 224.760 36.490 225.760 ;
    END
  END uio_oe[5]
  PIN uio_oe[6]
    DIRECTION OUTPUT ;
    USE SIGNAL ;
    PORT
      LAYER met4 ;
        RECT 33.430 224.760 33.730 225.760 ;
    END
  END uio_oe[6]
  PIN uio_oe[7]
    DIRECTION OUTPUT ;
    USE SIGNAL ;
    PORT
      LAYER met4 ;
        RECT 30.670 224.760 30.970 225.760 ;
    END
  END uio_oe[7]
  PIN uio_out[0]
    DIRECTION OUTPUT ;
    USE SIGNAL ;
    PORT
      LAYER met4 ;
        RECT 72.070 224.760 72.370 225.760 ;
    END
  END uio_out[0]
  PIN uio_out[1]
    DIRECTION OUTPUT ;
    USE SIGNAL ;
    PORT
      LAYER met4 ;
        RECT 69.310 224.760 69.610 225.760 ;
    END
  END uio_out[1]
  PIN uio_out[2]
    DIRECTION OUTPUT ;
    USE SIGNAL ;
    PORT
      LAYER met4 ;
        RECT 66.550 224.760 66.850 225.760 ;
    END
  END uio_out[2]
  PIN uio_out[3]
    DIRECTION OUTPUT ;
    USE SIGNAL ;
    PORT
      LAYER met4 ;
        RECT 63.790 224.760 64.090 225.760 ;
    END
  END uio_out[3]
  PIN uio_out[4]
    DIRECTION OUTPUT ;
    USE SIGNAL ;
    PORT
      LAYER met4 ;
        RECT 61.030 224.760 61.330 225.760 ;
    END
  END uio_out[4]
  PIN uio_out[5]
    DIRECTION OUTPUT ;
    USE SIGNAL ;
    PORT
      LAYER met4 ;
        RECT 58.270 224.760 58.570 225.760 ;
    END
  END uio_out[5]
  PIN uio_out[6]
    DIRECTION OUTPUT ;
    USE SIGNAL ;
    PORT
      LAYER met4 ;
        RECT 55.510 224.760 55.810 225.760 ;
    END
  END uio_out[6]
  PIN uio_out[7]
    DIRECTION OUTPUT ;
    USE SIGNAL ;
    PORT
      LAYER met4 ;
        RECT 52.750 224.760 53.050 225.760 ;
    END
  END uio_out[7]
  PIN uo_out[0]
    DIRECTION OUTPUT ;
    USE SIGNAL ;
    PORT
      LAYER met4 ;
        RECT 94.150 224.760 94.450 225.760 ;
    END
  END uo_out[0]
  PIN uo_out[1]
    DIRECTION OUTPUT ;
    USE SIGNAL ;
    PORT
      LAYER met4 ;
        RECT 91.390 224.760 91.690 225.760 ;
    END
  END uo_out[1]
  PIN uo_out[2]
    DIRECTION OUTPUT ;
    USE SIGNAL ;
    PORT
      LAYER met4 ;
        RECT 88.630 224.760 88.930 225.760 ;
    END
  END uo_out[2]
  PIN uo_out[3]
    DIRECTION OUTPUT ;
    USE SIGNAL ;
    PORT
      LAYER met4 ;
        RECT 85.870 224.760 86.170 225.760 ;
    END
  END uo_out[3]
  PIN uo_out[4]
    DIRECTION OUTPUT ;
    USE SIGNAL ;
    PORT
      LAYER met4 ;
        RECT 83.110 224.760 83.410 225.760 ;
    END
  END uo_out[4]
  PIN uo_out[5]
    DIRECTION OUTPUT ;
    USE SIGNAL ;
    PORT
      LAYER met4 ;
        RECT 80.350 224.760 80.650 225.760 ;
    END
  END uo_out[5]
  PIN uo_out[6]
    DIRECTION OUTPUT ;
    USE SIGNAL ;
    PORT
      LAYER met4 ;
        RECT 77.590 224.760 77.890 225.760 ;
    END
  END uo_out[6]
  PIN uo_out[7]
    DIRECTION OUTPUT ;
    USE SIGNAL ;
    PORT
      LAYER met4 ;
        RECT 74.830 224.760 75.130 225.760 ;
    END
  END uo_out[7]
  PIN VDPWR
    DIRECTION INOUT ;
    USE POWER ;
    PORT
      LAYER met4 ;
        RECT 1.000 5.000 3.000 220.760 ;
    END
  END VDPWR
  PIN VGND
    DIRECTION INOUT ;
    USE GROUND ;
    PORT
      LAYER met4 ;
        RECT 4.000 5.000 6.000 220.760 ;
    END
  END VGND
  OBS
      LAYER pwell ;
        RECT 59.565 57.865 78.755 60.175 ;
      LAYER nwell ;
        RECT 57.055 55.545 80.425 57.855 ;
      LAYER pwell ;
        RECT 59.375 52.575 78.565 54.885 ;
      LAYER nwell ;
        RECT 56.865 50.255 80.235 52.565 ;
        RECT 43.915 20.305 45.520 28.965 ;
      LAYER pwell ;
        RECT 45.910 28.630 46.720 28.770 ;
        RECT 45.910 28.460 46.910 28.630 ;
        RECT 45.910 26.940 46.720 28.460 ;
        RECT 46.930 27.620 47.840 28.570 ;
        RECT 45.810 26.790 46.720 26.920 ;
        RECT 46.930 26.790 47.750 27.620 ;
        RECT 45.810 26.640 47.750 26.790 ;
        RECT 45.810 26.620 46.910 26.640 ;
        RECT 45.810 25.570 46.720 26.620 ;
        RECT 46.930 25.540 47.840 26.470 ;
        RECT 45.810 25.410 46.720 25.540 ;
        RECT 45.810 25.240 46.910 25.410 ;
        RECT 45.810 24.190 46.720 25.240 ;
        RECT 45.810 24.030 46.720 24.160 ;
        RECT 46.930 24.030 47.610 25.540 ;
        RECT 45.810 23.860 47.610 24.030 ;
        RECT 45.810 22.810 46.720 23.860 ;
        RECT 46.930 23.720 47.610 23.860 ;
        RECT 46.930 22.780 47.840 23.710 ;
        RECT 45.850 22.350 46.635 22.780 ;
        RECT 45.910 22.190 46.720 22.330 ;
        RECT 45.910 22.020 46.910 22.190 ;
        RECT 45.910 20.500 46.720 22.020 ;
        RECT 46.930 21.270 47.610 22.780 ;
        RECT 46.740 21.100 47.610 21.270 ;
        RECT 46.930 20.960 47.610 21.100 ;
        RECT 47.015 20.510 47.800 20.940 ;
        RECT 46.930 19.340 47.840 20.290 ;
        RECT 46.930 18.510 47.750 19.340 ;
        RECT 46.740 18.360 47.750 18.510 ;
      LAYER nwell ;
        RECT 48.130 18.465 50.960 28.965 ;
      LAYER pwell ;
        RECT 51.350 28.630 52.160 28.770 ;
        RECT 51.350 28.460 52.350 28.630 ;
        RECT 51.350 26.940 52.160 28.460 ;
        RECT 56.985 27.635 59.295 46.825 ;
        RECT 51.290 26.490 52.075 26.920 ;
        RECT 51.250 26.330 52.160 26.460 ;
        RECT 51.250 26.160 52.350 26.330 ;
        RECT 51.250 25.110 52.160 26.160 ;
      LAYER nwell ;
        RECT 59.305 25.125 61.615 48.495 ;
      LAYER pwell ;
        RECT 62.335 27.625 64.645 46.815 ;
      LAYER nwell ;
        RECT 64.655 25.115 66.965 48.485 ;
      LAYER pwell ;
        RECT 67.685 27.655 69.995 46.845 ;
      LAYER nwell ;
        RECT 70.005 25.145 72.315 48.515 ;
      LAYER pwell ;
        RECT 72.965 27.615 75.275 46.805 ;
      LAYER nwell ;
        RECT 75.285 25.105 77.595 48.475 ;
      LAYER pwell ;
        RECT 78.555 27.625 80.865 46.815 ;
      LAYER nwell ;
        RECT 80.875 25.115 83.185 48.485 ;
      LAYER pwell ;
        RECT 83.905 27.615 86.215 46.805 ;
      LAYER nwell ;
        RECT 86.225 25.105 88.535 48.475 ;
      LAYER pwell ;
        RECT 89.255 27.645 91.565 46.835 ;
      LAYER nwell ;
        RECT 91.575 25.135 93.885 48.505 ;
      LAYER pwell ;
        RECT 94.535 27.605 96.845 46.795 ;
      LAYER nwell ;
        RECT 96.855 25.095 99.165 48.465 ;
      LAYER pwell ;
        RECT 51.250 24.950 52.160 25.080 ;
        RECT 51.250 24.780 52.350 24.950 ;
        RECT 51.250 23.730 52.160 24.780 ;
        RECT 51.290 23.270 52.075 23.700 ;
        RECT 51.250 23.110 52.160 23.240 ;
        RECT 51.250 22.940 52.350 23.110 ;
        RECT 51.250 21.890 52.160 22.940 ;
        RECT 51.250 21.730 52.160 21.860 ;
        RECT 51.250 21.560 52.350 21.730 ;
        RECT 51.250 20.510 52.160 21.560 ;
        RECT 51.350 20.350 52.160 20.490 ;
        RECT 51.350 20.180 52.350 20.350 ;
        RECT 51.350 18.660 52.160 20.180 ;
        RECT 46.740 18.340 46.910 18.360 ;
      LAYER nwell ;
        RECT 48.130 18.005 49.735 18.465 ;
      LAYER pwell ;
        RECT 44.580 9.620 47.680 12.580 ;
        RECT 47.750 9.630 49.960 12.730 ;
        RECT 57.430 9.640 60.530 12.600 ;
        RECT 60.600 9.650 62.810 12.750 ;
        RECT 70.440 9.710 73.540 12.670 ;
        RECT 73.610 9.720 75.820 12.820 ;
        RECT 83.290 9.640 86.390 12.600 ;
        RECT 86.460 9.650 88.670 12.750 ;
        RECT 96.410 9.590 99.510 12.550 ;
        RECT 99.580 9.600 101.790 12.700 ;
        RECT 109.310 9.540 112.410 12.500 ;
        RECT 112.480 9.550 114.690 12.650 ;
        RECT 123.050 9.500 126.150 12.460 ;
        RECT 126.220 9.510 128.430 12.610 ;
        RECT 136.140 9.500 139.240 12.460 ;
        RECT 139.310 9.510 141.520 12.610 ;
      LAYER li1 ;
        RECT 58.575 59.995 78.565 60.315 ;
        RECT 58.575 59.825 78.575 59.995 ;
        RECT 58.575 59.165 59.915 59.825 ;
        RECT 60.595 59.255 68.635 59.425 ;
        RECT 69.685 59.255 77.725 59.425 ;
        RECT 59.065 58.215 59.915 59.165 ;
        RECT 78.405 58.215 78.575 59.825 ;
        RECT 79.455 58.805 80.315 58.815 ;
        RECT 79.455 58.545 80.415 58.805 ;
        RECT 59.065 58.055 78.575 58.215 ;
        RECT 59.745 58.045 78.575 58.055 ;
        RECT 79.405 57.865 80.415 58.545 ;
        RECT 57.675 57.675 80.415 57.865 ;
        RECT 57.235 57.505 80.415 57.675 ;
        RECT 57.235 55.895 57.405 57.505 ;
        RECT 57.745 56.525 57.915 56.875 ;
        RECT 68.385 56.525 68.555 56.875 ;
        RECT 68.925 56.525 69.095 56.875 ;
        RECT 79.565 56.525 79.735 56.875 ;
        RECT 58.130 56.295 68.170 56.465 ;
        RECT 69.310 56.295 79.350 56.465 ;
        RECT 80.075 55.895 80.415 57.505 ;
        RECT 57.235 55.735 80.415 55.895 ;
        RECT 57.235 55.725 80.245 55.735 ;
        RECT 58.385 54.705 78.375 55.025 ;
        RECT 58.385 54.535 78.385 54.705 ;
        RECT 58.385 53.875 59.725 54.535 ;
        RECT 60.405 53.965 68.445 54.135 ;
        RECT 69.495 53.965 77.535 54.135 ;
        RECT 58.875 52.925 59.725 53.875 ;
        RECT 60.065 53.555 60.235 53.905 ;
        RECT 68.615 53.555 68.785 53.905 ;
        RECT 69.155 53.555 69.325 53.905 ;
        RECT 77.705 53.555 77.875 53.905 ;
        RECT 78.215 52.925 78.385 54.535 ;
        RECT 79.265 53.515 80.125 53.525 ;
        RECT 79.265 53.255 80.225 53.515 ;
        RECT 58.875 52.765 78.385 52.925 ;
        RECT 59.555 52.755 78.385 52.765 ;
        RECT 79.215 52.575 80.225 53.255 ;
        RECT 57.485 52.385 80.225 52.575 ;
        RECT 57.045 52.215 80.225 52.385 ;
        RECT 57.045 50.605 57.215 52.215 ;
        RECT 57.940 51.005 67.980 51.175 ;
        RECT 69.120 51.005 79.160 51.175 ;
        RECT 79.885 50.605 80.225 52.215 ;
        RECT 57.045 50.445 80.225 50.605 ;
        RECT 57.045 50.435 80.055 50.445 ;
        RECT 58.355 48.385 61.425 48.485 ;
        RECT 58.345 48.315 61.425 48.385 ;
        RECT 63.705 48.375 66.775 48.475 ;
        RECT 69.055 48.405 72.125 48.505 ;
        RECT 58.345 48.145 61.435 48.315 ;
        RECT 58.345 47.525 59.655 48.145 ;
        RECT 60.285 47.635 60.635 47.805 ;
        RECT 58.615 47.475 59.655 47.525 ;
        RECT 57.165 46.635 59.115 46.645 ;
        RECT 56.845 46.475 59.115 46.635 ;
        RECT 44.020 28.690 44.190 28.775 ;
        RECT 46.740 28.690 46.910 28.775 ;
        RECT 47.425 28.690 48.565 28.695 ;
        RECT 49.460 28.690 49.630 28.775 ;
        RECT 52.180 28.690 52.350 28.775 ;
        RECT 44.020 27.770 45.280 28.690 ;
        RECT 45.450 27.960 46.910 28.690 ;
        RECT 47.080 28.440 49.290 28.690 ;
        RECT 47.080 28.130 47.370 28.440 ;
        RECT 47.820 28.150 48.150 28.270 ;
        RECT 48.740 28.230 49.290 28.440 ;
        RECT 47.540 27.980 48.570 28.150 ;
        RECT 49.460 28.040 50.720 28.690 ;
        RECT 45.450 27.940 47.370 27.960 ;
        RECT 44.020 27.020 45.800 27.770 ;
        RECT 45.970 27.710 47.370 27.940 ;
        RECT 45.970 27.020 46.910 27.710 ;
        RECT 47.540 27.090 47.730 27.980 ;
        RECT 47.900 27.470 48.150 27.810 ;
        RECT 48.400 27.510 48.570 27.980 ;
        RECT 48.740 27.770 50.720 28.040 ;
        RECT 50.890 27.940 52.350 28.690 ;
        RECT 48.740 27.710 51.240 27.770 ;
        RECT 44.020 26.810 44.190 27.020 ;
        RECT 46.740 26.810 46.910 27.020 ;
        RECT 44.020 26.580 45.330 26.810 ;
        RECT 45.920 26.580 46.910 26.810 ;
        RECT 47.180 26.760 47.730 27.090 ;
        RECT 47.900 26.840 48.150 27.250 ;
        RECT 48.400 27.210 49.120 27.510 ;
        RECT 49.460 27.040 51.240 27.710 ;
        RECT 48.790 27.020 51.240 27.040 ;
        RECT 51.410 27.020 52.350 27.940 ;
        RECT 48.790 26.850 49.630 27.020 ;
        RECT 52.180 26.850 52.350 27.020 ;
        RECT 44.020 25.910 44.190 26.580 ;
        RECT 44.360 26.330 45.340 26.410 ;
        RECT 45.940 26.330 46.570 26.410 ;
        RECT 44.360 26.080 46.570 26.330 ;
        RECT 45.455 26.055 45.755 26.080 ;
        RECT 46.740 25.960 46.910 26.580 ;
        RECT 47.900 26.575 48.510 26.840 ;
        RECT 48.790 26.760 50.795 26.850 ;
        RECT 49.460 26.560 50.795 26.760 ;
        RECT 51.455 26.560 52.350 26.850 ;
        RECT 56.845 27.985 57.335 46.475 ;
        RECT 57.965 45.965 58.315 46.135 ;
        RECT 57.735 37.755 57.905 45.795 ;
        RECT 58.375 37.755 58.545 45.795 ;
        RECT 57.965 37.415 58.315 37.585 ;
        RECT 57.965 36.875 58.315 37.045 ;
        RECT 57.735 28.665 57.905 36.705 ;
        RECT 58.375 28.665 58.545 36.705 ;
        RECT 57.965 28.325 58.315 28.495 ;
        RECT 58.945 27.985 59.115 46.475 ;
        RECT 56.845 27.815 59.115 27.985 ;
        RECT 56.845 27.135 59.105 27.815 ;
        RECT 56.845 26.645 57.995 27.135 ;
        RECT 47.080 26.195 49.190 26.370 ;
        RECT 47.080 26.130 47.600 26.195 ;
        RECT 48.405 26.065 49.190 26.195 ;
        RECT 49.460 26.350 49.630 26.560 ;
        RECT 49.460 26.120 50.770 26.350 ;
        RECT 46.740 25.910 47.405 25.960 ;
        RECT 44.020 25.700 45.330 25.910 ;
        RECT 45.920 25.700 47.405 25.910 ;
        RECT 44.020 25.430 44.190 25.700 ;
        RECT 46.740 25.565 47.405 25.700 ;
        RECT 47.770 25.595 48.150 26.020 ;
        RECT 49.460 25.885 49.630 26.120 ;
        RECT 50.940 26.040 51.190 26.370 ;
        RECT 52.180 26.350 52.350 26.560 ;
        RECT 51.360 26.120 52.350 26.350 ;
        RECT 46.740 25.430 46.910 25.565 ;
        RECT 44.020 25.200 45.330 25.430 ;
        RECT 45.920 25.200 46.910 25.430 ;
        RECT 47.770 25.205 48.300 25.595 ;
        RECT 44.020 24.530 44.190 25.200 ;
        RECT 44.360 24.950 45.340 25.030 ;
        RECT 45.940 24.950 46.570 25.030 ;
        RECT 44.360 24.700 46.570 24.950 ;
        RECT 46.740 24.530 46.910 25.200 ;
        RECT 47.240 25.035 48.300 25.205 ;
        RECT 48.990 25.450 49.630 25.885 ;
        RECT 49.800 25.870 50.780 25.950 ;
        RECT 51.380 25.870 52.010 25.950 ;
        RECT 49.800 25.620 52.010 25.870 ;
        RECT 52.180 25.450 52.350 26.120 ;
        RECT 59.295 25.745 59.655 47.475 ;
        RECT 60.055 37.380 60.225 47.420 ;
        RECT 60.695 37.380 60.865 47.420 ;
        RECT 60.285 36.995 60.635 37.165 ;
        RECT 60.285 36.455 60.635 36.625 ;
        RECT 60.055 26.200 60.225 36.240 ;
        RECT 60.695 26.200 60.865 36.240 ;
        RECT 60.285 25.815 60.635 25.985 ;
        RECT 48.990 25.240 50.770 25.450 ;
        RECT 51.360 25.240 52.350 25.450 ;
        RECT 59.485 25.475 59.655 25.745 ;
        RECT 61.265 25.475 61.435 48.145 ;
        RECT 63.695 48.305 66.775 48.375 ;
        RECT 69.045 48.335 72.125 48.405 ;
        RECT 74.335 48.365 77.405 48.465 ;
        RECT 79.925 48.375 82.995 48.475 ;
        RECT 63.695 48.135 66.785 48.305 ;
        RECT 63.695 47.515 65.005 48.135 ;
        RECT 65.635 47.625 65.985 47.795 ;
        RECT 63.965 47.465 65.005 47.515 ;
        RECT 62.515 46.625 64.465 46.635 ;
        RECT 62.195 46.465 64.465 46.625 ;
        RECT 62.195 27.975 62.685 46.465 ;
        RECT 63.315 45.955 63.665 46.125 ;
        RECT 63.085 37.745 63.255 45.785 ;
        RECT 63.725 37.745 63.895 45.785 ;
        RECT 63.315 37.405 63.665 37.575 ;
        RECT 63.315 36.865 63.665 37.035 ;
        RECT 63.085 28.655 63.255 36.695 ;
        RECT 63.725 28.655 63.895 36.695 ;
        RECT 63.315 28.315 63.665 28.485 ;
        RECT 64.295 27.975 64.465 46.465 ;
        RECT 62.195 27.805 64.465 27.975 ;
        RECT 62.195 27.125 64.455 27.805 ;
        RECT 62.195 26.635 63.345 27.125 ;
        RECT 64.645 25.735 65.005 47.465 ;
        RECT 65.405 37.370 65.575 47.410 ;
        RECT 66.045 37.370 66.215 47.410 ;
        RECT 65.635 36.985 65.985 37.155 ;
        RECT 65.635 36.445 65.985 36.615 ;
        RECT 65.405 26.190 65.575 36.230 ;
        RECT 66.045 26.190 66.215 36.230 ;
        RECT 65.635 25.805 65.985 25.975 ;
        RECT 59.485 25.305 61.435 25.475 ;
        RECT 64.835 25.465 65.005 25.735 ;
        RECT 66.615 25.465 66.785 48.135 ;
        RECT 69.045 48.165 72.135 48.335 ;
        RECT 69.045 47.545 70.355 48.165 ;
        RECT 70.985 47.655 71.335 47.825 ;
        RECT 69.315 47.495 70.355 47.545 ;
        RECT 67.865 46.655 69.815 46.665 ;
        RECT 67.545 46.495 69.815 46.655 ;
        RECT 67.545 28.005 68.035 46.495 ;
        RECT 68.665 45.985 69.015 46.155 ;
        RECT 68.435 37.775 68.605 45.815 ;
        RECT 69.075 37.775 69.245 45.815 ;
        RECT 68.665 37.435 69.015 37.605 ;
        RECT 68.665 36.895 69.015 37.065 ;
        RECT 68.435 28.685 68.605 36.725 ;
        RECT 69.075 28.685 69.245 36.725 ;
        RECT 68.665 28.345 69.015 28.515 ;
        RECT 69.645 28.005 69.815 46.495 ;
        RECT 67.545 27.835 69.815 28.005 ;
        RECT 67.545 27.155 69.805 27.835 ;
        RECT 67.545 26.665 68.695 27.155 ;
        RECT 69.995 25.765 70.355 47.495 ;
        RECT 70.755 37.400 70.925 47.440 ;
        RECT 71.395 37.400 71.565 47.440 ;
        RECT 70.985 37.015 71.335 37.185 ;
        RECT 70.985 36.475 71.335 36.645 ;
        RECT 70.755 26.220 70.925 36.260 ;
        RECT 71.395 26.220 71.565 36.260 ;
        RECT 70.985 25.835 71.335 26.005 ;
        RECT 64.835 25.295 66.785 25.465 ;
        RECT 70.185 25.495 70.355 25.765 ;
        RECT 71.965 25.495 72.135 48.165 ;
        RECT 74.325 48.295 77.405 48.365 ;
        RECT 79.915 48.305 82.995 48.375 ;
        RECT 85.275 48.365 88.345 48.465 ;
        RECT 90.625 48.395 93.695 48.495 ;
        RECT 74.325 48.125 77.415 48.295 ;
        RECT 74.325 47.505 75.635 48.125 ;
        RECT 76.265 47.615 76.615 47.785 ;
        RECT 74.595 47.455 75.635 47.505 ;
        RECT 73.145 46.615 75.095 46.625 ;
        RECT 72.825 46.455 75.095 46.615 ;
        RECT 72.825 27.965 73.315 46.455 ;
        RECT 73.945 45.945 74.295 46.115 ;
        RECT 73.715 37.735 73.885 45.775 ;
        RECT 74.355 37.735 74.525 45.775 ;
        RECT 73.945 37.395 74.295 37.565 ;
        RECT 73.945 36.855 74.295 37.025 ;
        RECT 73.715 28.645 73.885 36.685 ;
        RECT 74.355 28.645 74.525 36.685 ;
        RECT 73.945 28.305 74.295 28.475 ;
        RECT 74.925 27.965 75.095 46.455 ;
        RECT 72.825 27.795 75.095 27.965 ;
        RECT 72.825 27.115 75.085 27.795 ;
        RECT 72.825 26.625 73.975 27.115 ;
        RECT 75.275 25.725 75.635 47.455 ;
        RECT 76.035 37.360 76.205 47.400 ;
        RECT 76.675 37.360 76.845 47.400 ;
        RECT 76.265 36.975 76.615 37.145 ;
        RECT 76.265 36.435 76.615 36.605 ;
        RECT 76.035 26.180 76.205 36.220 ;
        RECT 76.675 26.180 76.845 36.220 ;
        RECT 76.265 25.795 76.615 25.965 ;
        RECT 70.185 25.325 72.135 25.495 ;
        RECT 75.465 25.455 75.635 25.725 ;
        RECT 77.245 25.455 77.415 48.125 ;
        RECT 79.915 48.135 83.005 48.305 ;
        RECT 79.915 47.515 81.225 48.135 ;
        RECT 81.855 47.625 82.205 47.795 ;
        RECT 80.185 47.465 81.225 47.515 ;
        RECT 78.735 46.625 80.685 46.635 ;
        RECT 78.415 46.465 80.685 46.625 ;
        RECT 78.415 27.975 78.905 46.465 ;
        RECT 79.535 45.955 79.885 46.125 ;
        RECT 79.305 37.745 79.475 45.785 ;
        RECT 79.945 37.745 80.115 45.785 ;
        RECT 79.535 37.405 79.885 37.575 ;
        RECT 79.535 36.865 79.885 37.035 ;
        RECT 79.305 28.655 79.475 36.695 ;
        RECT 79.945 28.655 80.115 36.695 ;
        RECT 79.535 28.315 79.885 28.485 ;
        RECT 80.515 27.975 80.685 46.465 ;
        RECT 78.415 27.805 80.685 27.975 ;
        RECT 78.415 27.125 80.675 27.805 ;
        RECT 78.415 26.635 79.565 27.125 ;
        RECT 80.865 25.735 81.225 47.465 ;
        RECT 81.625 37.370 81.795 47.410 ;
        RECT 82.265 37.370 82.435 47.410 ;
        RECT 81.855 36.985 82.205 37.155 ;
        RECT 81.855 36.445 82.205 36.615 ;
        RECT 81.625 26.190 81.795 36.230 ;
        RECT 82.265 26.190 82.435 36.230 ;
        RECT 81.855 25.805 82.205 25.975 ;
        RECT 75.465 25.285 77.415 25.455 ;
        RECT 81.055 25.465 81.225 25.735 ;
        RECT 82.835 25.465 83.005 48.135 ;
        RECT 85.265 48.295 88.345 48.365 ;
        RECT 90.615 48.325 93.695 48.395 ;
        RECT 95.905 48.355 98.975 48.455 ;
        RECT 85.265 48.125 88.355 48.295 ;
        RECT 85.265 47.505 86.575 48.125 ;
        RECT 87.205 47.615 87.555 47.785 ;
        RECT 85.535 47.455 86.575 47.505 ;
        RECT 84.085 46.615 86.035 46.625 ;
        RECT 83.765 46.455 86.035 46.615 ;
        RECT 83.765 27.965 84.255 46.455 ;
        RECT 84.885 45.945 85.235 46.115 ;
        RECT 84.655 37.735 84.825 45.775 ;
        RECT 85.295 37.735 85.465 45.775 ;
        RECT 84.885 37.395 85.235 37.565 ;
        RECT 84.885 36.855 85.235 37.025 ;
        RECT 84.655 28.645 84.825 36.685 ;
        RECT 85.295 28.645 85.465 36.685 ;
        RECT 84.885 28.305 85.235 28.475 ;
        RECT 85.865 27.965 86.035 46.455 ;
        RECT 83.765 27.795 86.035 27.965 ;
        RECT 83.765 27.115 86.025 27.795 ;
        RECT 83.765 26.625 84.915 27.115 ;
        RECT 86.215 25.725 86.575 47.455 ;
        RECT 86.975 37.360 87.145 47.400 ;
        RECT 87.615 37.360 87.785 47.400 ;
        RECT 87.205 36.975 87.555 37.145 ;
        RECT 87.205 36.435 87.555 36.605 ;
        RECT 86.975 26.180 87.145 36.220 ;
        RECT 87.615 26.180 87.785 36.220 ;
        RECT 87.205 25.795 87.555 25.965 ;
        RECT 81.055 25.295 83.005 25.465 ;
        RECT 86.405 25.455 86.575 25.725 ;
        RECT 88.185 25.455 88.355 48.125 ;
        RECT 90.615 48.155 93.705 48.325 ;
        RECT 90.615 47.535 91.925 48.155 ;
        RECT 92.555 47.645 92.905 47.815 ;
        RECT 90.885 47.485 91.925 47.535 ;
        RECT 89.435 46.645 91.385 46.655 ;
        RECT 89.115 46.485 91.385 46.645 ;
        RECT 89.115 27.995 89.605 46.485 ;
        RECT 90.235 45.975 90.585 46.145 ;
        RECT 90.005 37.765 90.175 45.805 ;
        RECT 90.645 37.765 90.815 45.805 ;
        RECT 90.235 37.425 90.585 37.595 ;
        RECT 90.235 36.885 90.585 37.055 ;
        RECT 90.005 28.675 90.175 36.715 ;
        RECT 90.645 28.675 90.815 36.715 ;
        RECT 90.235 28.335 90.585 28.505 ;
        RECT 91.215 27.995 91.385 46.485 ;
        RECT 89.115 27.825 91.385 27.995 ;
        RECT 89.115 27.145 91.375 27.825 ;
        RECT 89.115 26.655 90.265 27.145 ;
        RECT 91.565 25.755 91.925 47.485 ;
        RECT 92.325 37.390 92.495 47.430 ;
        RECT 92.965 37.390 93.135 47.430 ;
        RECT 92.555 37.005 92.905 37.175 ;
        RECT 92.555 36.465 92.905 36.635 ;
        RECT 92.325 26.210 92.495 36.250 ;
        RECT 92.965 26.210 93.135 36.250 ;
        RECT 92.555 25.825 92.905 25.995 ;
        RECT 86.405 25.285 88.355 25.455 ;
        RECT 91.755 25.485 91.925 25.755 ;
        RECT 93.535 25.485 93.705 48.155 ;
        RECT 95.895 48.285 98.975 48.355 ;
        RECT 95.895 48.115 98.985 48.285 ;
        RECT 95.895 47.495 97.205 48.115 ;
        RECT 97.835 47.605 98.185 47.775 ;
        RECT 96.165 47.445 97.205 47.495 ;
        RECT 94.715 46.605 96.665 46.615 ;
        RECT 94.395 46.445 96.665 46.605 ;
        RECT 94.395 27.955 94.885 46.445 ;
        RECT 95.515 45.935 95.865 46.105 ;
        RECT 95.285 37.725 95.455 45.765 ;
        RECT 95.925 37.725 96.095 45.765 ;
        RECT 95.515 37.385 95.865 37.555 ;
        RECT 95.515 36.845 95.865 37.015 ;
        RECT 95.285 28.635 95.455 36.675 ;
        RECT 95.925 28.635 96.095 36.675 ;
        RECT 95.515 28.295 95.865 28.465 ;
        RECT 96.495 27.955 96.665 46.445 ;
        RECT 94.395 27.785 96.665 27.955 ;
        RECT 94.395 27.105 96.655 27.785 ;
        RECT 94.395 26.615 95.545 27.105 ;
        RECT 96.845 25.715 97.205 47.445 ;
        RECT 97.605 37.350 97.775 47.390 ;
        RECT 98.245 37.350 98.415 47.390 ;
        RECT 97.835 36.965 98.185 37.135 ;
        RECT 97.835 36.425 98.185 36.595 ;
        RECT 97.605 26.170 97.775 36.210 ;
        RECT 98.245 26.170 98.415 36.210 ;
        RECT 97.835 25.785 98.185 25.955 ;
        RECT 91.755 25.315 93.705 25.485 ;
        RECT 97.035 25.445 97.205 25.715 ;
        RECT 98.815 25.445 98.985 48.115 ;
        RECT 97.035 25.275 98.985 25.445 ;
        RECT 48.990 25.200 49.630 25.240 ;
        RECT 47.240 25.000 47.435 25.035 ;
        RECT 47.095 24.830 47.435 25.000 ;
        RECT 48.130 25.020 48.300 25.035 ;
        RECT 47.630 24.565 47.960 24.865 ;
        RECT 48.130 24.735 49.245 25.020 ;
        RECT 49.460 24.970 49.630 25.200 ;
        RECT 49.460 24.740 50.770 24.970 ;
        RECT 47.630 24.550 48.840 24.565 ;
        RECT 49.460 24.560 49.630 24.740 ;
        RECT 50.940 24.660 51.190 24.990 ;
        RECT 52.180 24.970 52.350 25.240 ;
        RECT 51.360 24.740 52.350 24.970 ;
        RECT 44.020 24.320 45.330 24.530 ;
        RECT 45.920 24.320 46.910 24.530 ;
        RECT 44.020 24.050 44.190 24.320 ;
        RECT 46.740 24.140 46.910 24.320 ;
        RECT 47.105 24.330 48.840 24.550 ;
        RECT 47.105 24.310 47.480 24.330 ;
        RECT 46.740 24.050 47.415 24.140 ;
        RECT 44.020 23.820 45.330 24.050 ;
        RECT 45.920 23.820 47.415 24.050 ;
        RECT 48.610 24.060 48.840 24.330 ;
        RECT 49.010 24.230 49.630 24.560 ;
        RECT 49.800 24.490 50.780 24.570 ;
        RECT 51.380 24.490 52.010 24.570 ;
        RECT 49.800 24.240 52.010 24.490 ;
        RECT 49.460 24.070 49.630 24.230 ;
        RECT 52.180 24.070 52.350 24.740 ;
        RECT 48.610 23.890 49.270 24.060 ;
        RECT 44.020 23.150 44.190 23.820 ;
        RECT 46.740 23.805 47.415 23.820 ;
        RECT 49.460 23.860 50.770 24.070 ;
        RECT 51.360 23.860 52.350 24.070 ;
        RECT 44.360 23.570 45.340 23.650 ;
        RECT 45.940 23.570 46.570 23.650 ;
        RECT 44.360 23.320 46.570 23.570 ;
        RECT 45.505 23.225 45.745 23.320 ;
        RECT 46.740 23.200 46.910 23.805 ;
        RECT 49.460 23.630 49.630 23.860 ;
        RECT 52.180 23.630 52.350 23.860 ;
        RECT 47.080 23.435 49.190 23.610 ;
        RECT 47.080 23.370 47.600 23.435 ;
        RECT 48.405 23.305 49.190 23.435 ;
        RECT 49.460 23.340 50.795 23.630 ;
        RECT 51.455 23.340 52.350 23.630 ;
        RECT 46.740 23.150 47.405 23.200 ;
        RECT 44.020 22.940 45.330 23.150 ;
        RECT 45.920 22.940 47.405 23.150 ;
        RECT 44.020 22.710 44.190 22.940 ;
        RECT 46.740 22.805 47.405 22.940 ;
        RECT 47.770 22.835 48.150 23.260 ;
        RECT 49.460 23.130 49.630 23.340 ;
        RECT 49.460 23.125 50.770 23.130 ;
        RECT 48.990 22.900 50.770 23.125 ;
        RECT 46.740 22.710 46.910 22.805 ;
        RECT 44.020 22.420 45.355 22.710 ;
        RECT 46.015 22.420 46.910 22.710 ;
        RECT 47.770 22.445 48.300 22.835 ;
        RECT 44.020 22.250 44.190 22.420 ;
        RECT 46.740 22.250 46.910 22.420 ;
        RECT 44.020 21.330 45.280 22.250 ;
        RECT 45.450 21.500 46.910 22.250 ;
        RECT 47.240 22.275 48.300 22.445 ;
        RECT 48.990 22.440 49.630 22.900 ;
        RECT 50.940 22.820 51.190 23.150 ;
        RECT 52.180 23.130 52.350 23.340 ;
        RECT 51.360 22.900 52.350 23.130 ;
        RECT 47.240 22.240 47.435 22.275 ;
        RECT 47.095 22.070 47.435 22.240 ;
        RECT 48.130 22.260 48.300 22.275 ;
        RECT 47.630 21.805 47.960 22.105 ;
        RECT 48.130 21.975 49.245 22.260 ;
        RECT 49.460 22.230 49.630 22.440 ;
        RECT 49.800 22.650 50.780 22.730 ;
        RECT 51.380 22.650 52.010 22.730 ;
        RECT 49.800 22.400 52.010 22.650 ;
        RECT 52.180 22.230 52.350 22.900 ;
        RECT 49.460 22.020 50.770 22.230 ;
        RECT 51.360 22.020 52.350 22.230 ;
        RECT 47.630 21.790 48.840 21.805 ;
        RECT 49.460 21.800 49.630 22.020 ;
        RECT 47.105 21.570 48.840 21.790 ;
        RECT 47.105 21.550 47.480 21.570 ;
        RECT 45.970 21.380 46.910 21.500 ;
        RECT 44.020 20.580 45.800 21.330 ;
        RECT 45.970 21.045 47.415 21.380 ;
        RECT 48.610 21.300 48.840 21.570 ;
        RECT 49.010 21.750 49.630 21.800 ;
        RECT 50.945 21.770 51.185 21.795 ;
        RECT 49.010 21.520 50.770 21.750 ;
        RECT 49.010 21.470 49.630 21.520 ;
        RECT 48.610 21.130 49.270 21.300 ;
        RECT 45.970 20.870 46.910 21.045 ;
        RECT 49.460 20.870 49.630 21.470 ;
        RECT 50.940 21.440 51.190 21.770 ;
        RECT 52.180 21.750 52.350 22.020 ;
        RECT 51.360 21.520 52.350 21.750 ;
        RECT 49.800 21.270 50.780 21.350 ;
        RECT 51.380 21.270 52.010 21.350 ;
        RECT 49.800 21.020 52.010 21.270 ;
        RECT 45.970 20.580 47.635 20.870 ;
        RECT 48.295 20.850 49.630 20.870 ;
        RECT 52.180 20.850 52.350 21.520 ;
        RECT 48.295 20.640 50.770 20.850 ;
        RECT 51.360 20.640 52.350 20.850 ;
        RECT 48.295 20.580 49.630 20.640 ;
        RECT 44.020 20.495 44.190 20.580 ;
        RECT 46.740 19.680 46.910 20.580 ;
        RECT 49.460 20.410 49.630 20.580 ;
        RECT 52.180 20.410 52.350 20.640 ;
        RECT 47.080 20.160 49.290 20.410 ;
        RECT 47.080 19.850 47.370 20.160 ;
        RECT 47.820 19.870 48.150 19.990 ;
        RECT 48.740 19.950 49.290 20.160 ;
        RECT 47.540 19.700 48.570 19.870 ;
        RECT 49.460 19.760 50.720 20.410 ;
        RECT 46.740 19.430 47.370 19.680 ;
        RECT 46.740 18.195 46.910 19.430 ;
        RECT 47.540 18.810 47.730 19.700 ;
        RECT 48.400 19.230 48.570 19.700 ;
        RECT 48.740 19.490 50.720 19.760 ;
        RECT 50.890 19.660 52.350 20.410 ;
        RECT 48.740 19.430 51.240 19.490 ;
        RECT 48.400 18.930 49.120 19.230 ;
        RECT 47.180 18.480 47.730 18.810 ;
        RECT 49.460 18.760 51.240 19.430 ;
        RECT 48.790 18.740 51.240 18.760 ;
        RECT 51.410 18.740 52.350 19.660 ;
        RECT 48.790 18.480 49.630 18.740 ;
        RECT 52.180 18.655 52.350 18.740 ;
        RECT 49.460 18.195 49.630 18.480 ;
        RECT 44.760 12.230 47.500 12.400 ;
        RECT 44.760 9.970 44.930 12.230 ;
        RECT 45.610 11.660 46.650 11.830 ;
        RECT 45.610 10.370 46.650 10.540 ;
        RECT 47.330 9.970 47.500 12.230 ;
        RECT 47.930 12.380 49.780 12.550 ;
        RECT 47.930 10.020 48.100 12.380 ;
        RECT 48.690 11.870 49.020 12.040 ;
        RECT 48.500 10.660 48.670 11.700 ;
        RECT 48.690 10.320 49.020 10.490 ;
        RECT 44.760 9.940 47.500 9.970 ;
        RECT 44.740 9.800 47.500 9.940 ;
        RECT 47.870 9.980 48.300 10.020 ;
        RECT 49.610 9.980 49.780 12.380 ;
        RECT 47.870 9.810 49.780 9.980 ;
        RECT 57.610 12.250 60.350 12.420 ;
        RECT 57.610 9.990 57.780 12.250 ;
        RECT 58.460 11.680 59.500 11.850 ;
        RECT 58.460 10.390 59.500 10.560 ;
        RECT 60.180 9.990 60.350 12.250 ;
        RECT 60.780 12.400 62.630 12.570 ;
        RECT 60.780 10.040 60.950 12.400 ;
        RECT 61.540 11.890 61.870 12.060 ;
        RECT 61.350 10.680 61.520 11.720 ;
        RECT 61.540 10.340 61.870 10.510 ;
        RECT 57.610 9.960 60.350 9.990 ;
        RECT 57.590 9.820 60.350 9.960 ;
        RECT 60.720 10.000 61.150 10.040 ;
        RECT 62.460 10.000 62.630 12.400 ;
        RECT 70.620 12.320 73.360 12.490 ;
        RECT 70.620 10.060 70.790 12.320 ;
        RECT 71.470 11.750 72.510 11.920 ;
        RECT 71.470 10.460 72.510 10.630 ;
        RECT 73.190 10.060 73.360 12.320 ;
        RECT 73.790 12.470 75.640 12.640 ;
        RECT 73.790 10.110 73.960 12.470 ;
        RECT 74.550 11.960 74.880 12.130 ;
        RECT 74.360 10.750 74.530 11.790 ;
        RECT 74.550 10.410 74.880 10.580 ;
        RECT 70.620 10.030 73.360 10.060 ;
        RECT 60.720 9.830 62.630 10.000 ;
        RECT 70.600 9.890 73.360 10.030 ;
        RECT 73.730 10.070 74.160 10.110 ;
        RECT 75.470 10.070 75.640 12.470 ;
        RECT 73.730 9.900 75.640 10.070 ;
        RECT 83.470 12.250 86.210 12.420 ;
        RECT 83.470 9.990 83.640 12.250 ;
        RECT 84.320 11.680 85.360 11.850 ;
        RECT 84.320 10.390 85.360 10.560 ;
        RECT 86.040 9.990 86.210 12.250 ;
        RECT 86.640 12.400 88.490 12.570 ;
        RECT 86.640 10.040 86.810 12.400 ;
        RECT 87.400 11.890 87.730 12.060 ;
        RECT 87.210 10.680 87.380 11.720 ;
        RECT 87.400 10.340 87.730 10.510 ;
        RECT 83.470 9.960 86.210 9.990 ;
        RECT 44.740 9.500 45.700 9.800 ;
        RECT 47.870 9.500 48.300 9.810 ;
        RECT 57.590 9.520 58.550 9.820 ;
        RECT 60.720 9.520 61.150 9.830 ;
        RECT 70.600 9.590 71.560 9.890 ;
        RECT 73.730 9.590 74.160 9.900 ;
        RECT 44.570 8.860 48.300 9.500 ;
        RECT 57.420 8.880 61.150 9.520 ;
        RECT 70.430 8.950 74.160 9.590 ;
        RECT 83.450 9.820 86.210 9.960 ;
        RECT 86.580 10.000 87.010 10.040 ;
        RECT 88.320 10.000 88.490 12.400 ;
        RECT 86.580 9.830 88.490 10.000 ;
        RECT 96.590 12.200 99.330 12.370 ;
        RECT 96.590 9.940 96.760 12.200 ;
        RECT 97.440 11.630 98.480 11.800 ;
        RECT 97.440 10.340 98.480 10.510 ;
        RECT 99.160 9.940 99.330 12.200 ;
        RECT 99.760 12.350 101.610 12.520 ;
        RECT 99.760 9.990 99.930 12.350 ;
        RECT 100.520 11.840 100.850 12.010 ;
        RECT 100.330 10.630 100.500 11.670 ;
        RECT 100.520 10.290 100.850 10.460 ;
        RECT 96.590 9.910 99.330 9.940 ;
        RECT 83.450 9.520 84.410 9.820 ;
        RECT 86.580 9.520 87.010 9.830 ;
        RECT 70.430 8.910 74.130 8.950 ;
        RECT 83.280 8.880 87.010 9.520 ;
        RECT 96.570 9.770 99.330 9.910 ;
        RECT 99.700 9.950 100.130 9.990 ;
        RECT 101.440 9.950 101.610 12.350 ;
        RECT 99.700 9.780 101.610 9.950 ;
        RECT 109.490 12.150 112.230 12.320 ;
        RECT 109.490 9.890 109.660 12.150 ;
        RECT 110.340 11.580 111.380 11.750 ;
        RECT 110.340 10.290 111.380 10.460 ;
        RECT 112.060 9.890 112.230 12.150 ;
        RECT 112.660 12.300 114.510 12.470 ;
        RECT 112.660 9.940 112.830 12.300 ;
        RECT 113.420 11.790 113.750 11.960 ;
        RECT 113.230 10.580 113.400 11.620 ;
        RECT 113.420 10.240 113.750 10.410 ;
        RECT 109.490 9.860 112.230 9.890 ;
        RECT 96.570 9.470 97.530 9.770 ;
        RECT 99.700 9.470 100.130 9.780 ;
        RECT 44.570 8.820 48.270 8.860 ;
        RECT 57.420 8.840 61.120 8.880 ;
        RECT 83.280 8.840 86.980 8.880 ;
        RECT 96.400 8.830 100.130 9.470 ;
        RECT 109.470 9.720 112.230 9.860 ;
        RECT 112.600 9.900 113.030 9.940 ;
        RECT 114.340 9.900 114.510 12.300 ;
        RECT 112.600 9.730 114.510 9.900 ;
        RECT 123.230 12.110 125.970 12.280 ;
        RECT 123.230 9.850 123.400 12.110 ;
        RECT 124.080 11.540 125.120 11.710 ;
        RECT 124.080 10.250 125.120 10.420 ;
        RECT 125.800 9.850 125.970 12.110 ;
        RECT 126.400 12.260 128.250 12.430 ;
        RECT 126.400 9.900 126.570 12.260 ;
        RECT 127.160 11.750 127.490 11.920 ;
        RECT 126.970 10.540 127.140 11.580 ;
        RECT 127.160 10.200 127.490 10.370 ;
        RECT 123.230 9.820 125.970 9.850 ;
        RECT 109.470 9.420 110.430 9.720 ;
        RECT 112.600 9.420 113.030 9.730 ;
        RECT 96.400 8.790 100.100 8.830 ;
        RECT 109.300 8.780 113.030 9.420 ;
        RECT 123.210 9.680 125.970 9.820 ;
        RECT 126.340 9.860 126.770 9.900 ;
        RECT 128.080 9.860 128.250 12.260 ;
        RECT 126.340 9.690 128.250 9.860 ;
        RECT 136.320 12.110 139.060 12.280 ;
        RECT 136.320 9.850 136.490 12.110 ;
        RECT 137.170 11.540 138.210 11.710 ;
        RECT 137.170 10.250 138.210 10.420 ;
        RECT 138.890 9.850 139.060 12.110 ;
        RECT 139.490 12.260 141.340 12.430 ;
        RECT 139.490 9.900 139.660 12.260 ;
        RECT 140.250 11.750 140.580 11.920 ;
        RECT 140.060 10.540 140.230 11.580 ;
        RECT 140.250 10.200 140.580 10.370 ;
        RECT 136.320 9.820 139.060 9.850 ;
        RECT 123.210 9.380 124.170 9.680 ;
        RECT 126.340 9.380 126.770 9.690 ;
        RECT 136.300 9.680 139.060 9.820 ;
        RECT 139.430 9.860 139.860 9.900 ;
        RECT 141.170 9.860 141.340 12.260 ;
        RECT 139.430 9.690 141.340 9.860 ;
        RECT 136.300 9.380 137.260 9.680 ;
        RECT 139.430 9.380 139.860 9.690 ;
        RECT 109.300 8.740 113.000 8.780 ;
        RECT 123.040 8.740 126.770 9.380 ;
        RECT 136.130 8.740 139.860 9.380 ;
        RECT 123.040 8.700 126.740 8.740 ;
        RECT 136.130 8.700 139.830 8.740 ;
      LAYER met1 ;
        RECT 57.350 60.580 82.450 61.330 ;
        RECT 57.350 60.075 58.100 60.580 ;
        RECT 57.235 59.075 58.235 60.075 ;
        RECT 58.485 59.765 59.485 60.075 ;
        RECT 58.465 59.125 59.505 59.765 ;
        RECT 60.775 59.455 68.295 59.715 ;
        RECT 69.985 59.455 77.505 59.735 ;
        RECT 60.615 59.225 68.615 59.455 ;
        RECT 69.705 59.225 77.705 59.455 ;
        RECT 58.485 59.075 59.485 59.125 ;
        RECT 56.015 58.655 56.395 58.685 ;
        RECT 57.245 58.655 58.245 58.935 ;
        RECT 56.015 58.275 58.245 58.655 ;
        RECT 56.015 58.245 56.395 58.275 ;
        RECT 57.245 57.935 58.245 58.275 ;
        RECT 57.605 55.745 57.975 57.935 ;
        RECT 79.395 57.905 80.395 58.905 ;
        RECT 68.375 56.855 69.105 56.875 ;
        RECT 79.545 56.855 79.815 56.885 ;
        RECT 68.355 56.545 69.125 56.855 ;
        RECT 79.535 56.545 79.815 56.855 ;
        RECT 58.150 56.265 68.150 56.495 ;
        RECT 58.635 56.015 67.605 56.265 ;
        RECT 68.525 55.745 68.975 56.545 ;
        RECT 69.330 56.265 79.330 56.495 ;
        RECT 70.015 55.935 78.985 56.265 ;
        RECT 79.545 55.745 79.815 56.545 ;
        RECT 57.605 55.475 79.815 55.745 ;
        RECT 57.045 54.500 58.045 54.785 ;
        RECT 58.295 54.525 59.295 54.785 ;
        RECT 59.955 54.585 77.985 54.945 ;
        RECT 56.270 53.965 58.045 54.500 ;
        RECT 56.270 49.890 56.805 53.965 ;
        RECT 57.045 53.785 58.045 53.965 ;
        RECT 58.255 53.895 59.325 54.525 ;
        RECT 58.295 53.785 59.295 53.895 ;
        RECT 59.955 53.885 60.235 54.585 ;
        RECT 60.585 54.165 68.105 54.425 ;
        RECT 60.425 53.935 68.425 54.165 ;
        RECT 68.655 53.945 69.255 54.585 ;
        RECT 69.795 54.165 77.315 54.445 ;
        RECT 68.585 53.885 69.325 53.945 ;
        RECT 69.515 53.935 77.515 54.165 ;
        RECT 59.955 53.875 60.265 53.885 ;
        RECT 59.555 53.645 60.265 53.875 ;
        RECT 58.285 53.575 60.265 53.645 ;
        RECT 68.585 53.575 69.355 53.885 ;
        RECT 58.285 53.185 59.805 53.575 ;
        RECT 68.585 53.545 69.325 53.575 ;
        RECT 77.675 53.555 77.975 54.585 ;
        RECT 58.285 52.645 59.285 53.185 ;
        RECT 79.205 52.615 80.205 53.615 ;
        RECT 57.960 50.975 67.960 51.205 ;
        RECT 69.140 50.975 79.140 51.205 ;
        RECT 58.445 50.725 67.415 50.975 ;
        RECT 69.825 50.645 78.795 50.975 ;
        RECT 56.270 49.765 73.785 49.890 ;
        RECT 81.670 49.865 82.420 50.500 ;
        RECT 56.270 49.355 73.820 49.765 ;
        RECT 57.175 48.555 57.710 49.355 ;
        RECT 57.035 47.265 58.035 48.555 ;
        RECT 58.255 47.465 59.255 49.025 ;
        RECT 62.585 48.535 63.120 49.355 ;
        RECT 67.950 48.715 68.485 49.355 ;
        RECT 73.215 48.725 73.820 49.355 ;
        RECT 78.800 49.330 95.590 49.865 ;
        RECT 59.555 48.135 61.345 48.455 ;
        RECT 62.375 47.985 63.375 48.535 ;
        RECT 60.275 47.615 61.685 47.885 ;
        RECT 60.305 47.605 60.615 47.615 ;
        RECT 57.035 46.735 59.245 47.265 ;
        RECT 56.925 46.235 57.285 46.245 ;
        RECT 56.925 45.935 58.315 46.235 ;
        RECT 58.775 46.015 59.245 46.735 ;
        RECT 60.025 46.205 60.255 47.400 ;
        RECT 59.785 46.015 60.255 46.205 ;
        RECT 56.925 37.515 57.285 45.935 ;
        RECT 58.495 45.775 60.255 46.015 ;
        RECT 57.705 45.575 57.935 45.775 ;
        RECT 57.425 38.055 57.935 45.575 ;
        RECT 57.705 37.775 57.935 38.055 ;
        RECT 58.345 45.435 60.255 45.775 ;
        RECT 58.345 44.285 58.855 45.435 ;
        RECT 59.785 44.285 60.255 45.435 ;
        RECT 58.345 42.985 60.255 44.285 ;
        RECT 58.345 39.945 58.855 42.985 ;
        RECT 59.785 39.945 60.255 42.985 ;
        RECT 58.345 38.645 60.255 39.945 ;
        RECT 58.345 37.825 58.855 38.645 ;
        RECT 58.345 37.775 58.575 37.825 ;
        RECT 57.985 37.585 58.295 37.615 ;
        RECT 57.925 37.515 58.325 37.585 ;
        RECT 56.925 36.915 58.325 37.515 ;
        RECT 46.450 31.710 50.420 32.700 ;
        RECT 46.540 31.700 47.540 31.710 ;
        RECT 48.350 31.650 49.760 31.710 ;
        RECT 47.465 28.835 48.555 29.025 ;
        RECT 43.865 20.495 44.345 28.775 ;
        RECT 45.395 26.305 45.815 26.315 ;
        RECT 45.335 26.085 45.845 26.305 ;
        RECT 45.395 26.025 45.815 26.085 ;
        RECT 45.455 25.875 45.795 26.025 ;
        RECT 44.485 24.935 44.755 24.995 ;
        RECT 44.485 24.925 45.325 24.935 ;
        RECT 44.485 24.665 45.775 24.925 ;
        RECT 44.485 24.645 44.755 24.665 ;
        RECT 44.965 24.525 45.775 24.665 ;
        RECT 44.635 23.615 45.305 23.655 ;
        RECT 44.515 23.535 45.355 23.615 ;
        RECT 44.515 23.325 45.775 23.535 ;
        RECT 44.545 23.165 45.775 23.325 ;
        RECT 44.545 23.135 45.305 23.165 ;
        RECT 43.865 19.655 44.335 20.495 ;
        RECT 44.545 20.445 44.755 23.135 ;
        RECT 44.490 20.185 44.810 20.445 ;
        RECT 43.935 19.535 44.335 19.655 ;
        RECT 44.545 19.485 44.755 20.185 ;
        RECT 46.585 18.195 47.065 28.775 ;
        RECT 47.435 28.725 48.555 28.835 ;
        RECT 47.365 28.425 48.625 28.725 ;
        RECT 47.875 27.755 48.165 27.835 ;
        RECT 47.605 27.445 48.165 27.755 ;
        RECT 47.235 26.400 47.435 26.405 ;
        RECT 47.220 26.110 47.450 26.400 ;
        RECT 47.245 25.575 47.425 26.110 ;
        RECT 47.205 25.255 47.465 25.575 ;
        RECT 47.605 24.945 47.745 27.445 ;
        RECT 47.920 27.235 48.170 27.250 ;
        RECT 47.885 26.535 48.175 27.235 ;
        RECT 47.895 26.525 48.175 26.535 ;
        RECT 49.305 26.885 49.785 28.775 ;
        RECT 51.025 28.700 51.285 29.020 ;
        RECT 47.920 26.370 48.170 26.525 ;
        RECT 49.305 26.515 50.745 26.885 ;
        RECT 47.915 26.050 48.175 26.370 ;
        RECT 47.375 24.935 47.745 24.945 ;
        RECT 47.355 24.525 47.745 24.935 ;
        RECT 47.355 24.515 47.635 24.525 ;
        RECT 47.235 23.345 47.655 23.635 ;
        RECT 47.375 22.795 47.635 23.345 ;
        RECT 47.335 20.435 48.215 20.445 ;
        RECT 47.255 20.135 48.255 20.435 ;
        RECT 47.335 20.005 48.215 20.135 ;
        RECT 49.305 18.195 49.785 26.515 ;
        RECT 51.080 26.425 51.230 28.700 ;
        RECT 52.025 26.895 52.505 28.775 ;
        RECT 56.925 28.495 57.285 36.915 ;
        RECT 57.925 36.845 58.325 36.915 ;
        RECT 57.705 36.365 57.935 36.685 ;
        RECT 57.445 28.845 57.935 36.365 ;
        RECT 57.705 28.685 57.935 28.845 ;
        RECT 58.345 36.675 58.575 36.685 ;
        RECT 58.345 34.685 58.845 36.675 ;
        RECT 59.055 34.685 59.465 38.645 ;
        RECT 59.785 38.295 60.255 38.645 ;
        RECT 60.025 37.400 60.255 38.295 ;
        RECT 60.665 47.055 60.895 47.400 ;
        RECT 60.665 38.085 61.225 47.055 ;
        RECT 60.665 37.400 60.895 38.085 ;
        RECT 60.305 37.175 60.615 37.195 ;
        RECT 60.285 37.045 60.615 37.175 ;
        RECT 61.415 37.045 61.685 47.615 ;
        RECT 62.375 47.535 63.385 47.985 ;
        RECT 62.385 47.255 63.385 47.535 ;
        RECT 63.605 47.455 64.605 48.455 ;
        RECT 64.945 48.115 66.735 48.435 ;
        RECT 67.725 48.015 68.725 48.715 ;
        RECT 65.625 47.605 67.035 47.875 ;
        RECT 67.725 47.715 68.735 48.015 ;
        RECT 65.655 47.595 65.965 47.605 ;
        RECT 63.685 47.445 64.565 47.455 ;
        RECT 62.385 46.725 64.595 47.255 ;
        RECT 60.285 36.595 61.685 37.045 ;
        RECT 60.285 36.445 60.615 36.595 ;
        RECT 60.305 36.425 60.615 36.445 ;
        RECT 60.025 34.945 60.255 36.220 ;
        RECT 59.755 34.685 60.255 34.945 ;
        RECT 58.345 33.385 60.255 34.685 ;
        RECT 58.345 30.755 58.845 33.385 ;
        RECT 59.755 30.755 60.255 33.385 ;
        RECT 58.345 29.455 60.255 30.755 ;
        RECT 58.345 28.765 58.845 29.455 ;
        RECT 58.345 28.685 58.575 28.765 ;
        RECT 57.985 28.495 58.295 28.525 ;
        RECT 56.925 28.215 58.295 28.495 ;
        RECT 57.995 28.065 58.295 28.215 ;
        RECT 57.995 27.815 58.685 28.065 ;
        RECT 51.385 26.525 52.505 26.895 ;
        RECT 57.085 26.555 58.085 27.555 ;
        RECT 58.225 27.545 58.685 27.815 ;
        RECT 58.225 26.545 59.225 27.545 ;
        RECT 59.755 27.035 60.255 29.455 ;
        RECT 50.915 26.060 51.230 26.425 ;
        RECT 50.915 25.985 51.195 26.060 ;
        RECT 50.005 25.945 50.705 25.965 ;
        RECT 49.945 25.605 50.765 25.945 ;
        RECT 50.005 25.585 50.705 25.605 ;
        RECT 50.945 25.245 51.205 25.565 ;
        RECT 50.985 25.015 51.160 25.245 ;
        RECT 50.925 24.635 51.205 25.015 ;
        RECT 50.015 24.575 50.705 24.595 ;
        RECT 49.955 24.255 50.765 24.575 ;
        RECT 50.015 24.235 50.705 24.255 ;
        RECT 50.945 23.195 51.245 23.215 ;
        RECT 50.915 22.785 51.245 23.195 ;
        RECT 50.915 22.775 51.215 22.785 ;
        RECT 50.115 22.735 50.725 22.745 ;
        RECT 50.045 22.635 50.775 22.735 ;
        RECT 51.435 22.635 51.885 22.725 ;
        RECT 50.045 22.395 51.885 22.635 ;
        RECT 50.115 22.355 50.725 22.395 ;
        RECT 50.085 21.445 50.345 21.765 ;
        RECT 50.915 21.445 51.215 21.855 ;
        RECT 50.110 20.425 50.320 21.445 ;
        RECT 50.915 20.995 51.805 21.295 ;
        RECT 50.985 20.885 51.745 20.995 ;
        RECT 50.085 20.105 50.345 20.425 ;
        RECT 52.025 18.655 52.505 26.525 ;
        RECT 57.085 25.305 58.085 26.305 ;
        RECT 58.225 26.045 59.225 26.315 ;
        RECT 60.025 26.220 60.255 27.035 ;
        RECT 60.665 35.675 60.895 36.220 ;
        RECT 60.665 26.705 61.145 35.675 ;
        RECT 60.665 26.220 60.895 26.705 ;
        RECT 61.415 26.045 61.685 36.595 ;
        RECT 62.275 46.225 62.635 46.235 ;
        RECT 62.275 45.925 63.665 46.225 ;
        RECT 64.125 46.005 64.595 46.725 ;
        RECT 65.375 46.195 65.605 47.390 ;
        RECT 65.135 46.005 65.605 46.195 ;
        RECT 62.275 37.505 62.635 45.925 ;
        RECT 63.845 45.765 65.605 46.005 ;
        RECT 63.055 45.565 63.285 45.765 ;
        RECT 62.775 38.045 63.285 45.565 ;
        RECT 63.055 37.765 63.285 38.045 ;
        RECT 63.695 45.425 65.605 45.765 ;
        RECT 63.695 44.275 64.205 45.425 ;
        RECT 65.135 44.275 65.605 45.425 ;
        RECT 63.695 42.975 65.605 44.275 ;
        RECT 63.695 39.935 64.205 42.975 ;
        RECT 65.135 39.935 65.605 42.975 ;
        RECT 63.695 38.635 65.605 39.935 ;
        RECT 63.695 37.815 64.205 38.635 ;
        RECT 63.695 37.765 63.925 37.815 ;
        RECT 63.335 37.575 63.645 37.605 ;
        RECT 63.275 37.505 63.675 37.575 ;
        RECT 62.275 36.905 63.675 37.505 ;
        RECT 62.275 28.485 62.635 36.905 ;
        RECT 63.275 36.835 63.675 36.905 ;
        RECT 63.055 36.355 63.285 36.675 ;
        RECT 62.795 28.835 63.285 36.355 ;
        RECT 63.055 28.675 63.285 28.835 ;
        RECT 63.695 36.665 63.925 36.675 ;
        RECT 63.695 34.675 64.195 36.665 ;
        RECT 64.405 34.675 64.815 38.635 ;
        RECT 65.135 38.285 65.605 38.635 ;
        RECT 65.375 37.390 65.605 38.285 ;
        RECT 66.015 47.045 66.245 47.390 ;
        RECT 66.015 38.075 66.575 47.045 ;
        RECT 66.015 37.390 66.245 38.075 ;
        RECT 65.655 37.165 65.965 37.185 ;
        RECT 65.635 37.035 65.965 37.165 ;
        RECT 66.765 37.035 67.035 47.605 ;
        RECT 67.735 47.285 68.735 47.715 ;
        RECT 68.955 47.485 69.955 48.485 ;
        RECT 70.295 48.155 72.085 48.475 ;
        RECT 70.975 47.635 72.385 47.905 ;
        RECT 71.005 47.625 71.315 47.635 ;
        RECT 69.025 47.475 69.905 47.485 ;
        RECT 67.735 46.755 69.945 47.285 ;
        RECT 65.635 36.585 67.035 37.035 ;
        RECT 65.635 36.435 65.965 36.585 ;
        RECT 65.655 36.415 65.965 36.435 ;
        RECT 65.375 34.935 65.605 36.210 ;
        RECT 65.105 34.675 65.605 34.935 ;
        RECT 63.695 33.375 65.605 34.675 ;
        RECT 63.695 30.745 64.195 33.375 ;
        RECT 65.105 30.745 65.605 33.375 ;
        RECT 63.695 29.445 65.605 30.745 ;
        RECT 63.695 28.755 64.195 29.445 ;
        RECT 63.695 28.675 63.925 28.755 ;
        RECT 63.335 28.485 63.645 28.515 ;
        RECT 62.275 28.205 63.645 28.485 ;
        RECT 63.345 28.055 63.645 28.205 ;
        RECT 63.345 27.805 64.035 28.055 ;
        RECT 62.435 26.545 63.435 27.545 ;
        RECT 63.575 27.535 64.035 27.805 ;
        RECT 63.575 26.535 64.575 27.535 ;
        RECT 65.105 27.025 65.605 29.445 ;
        RECT 58.225 25.675 61.685 26.045 ;
        RECT 58.225 25.335 59.945 25.675 ;
        RECT 58.225 25.315 59.225 25.335 ;
        RECT 57.405 24.875 58.015 25.305 ;
        RECT 57.175 24.620 58.175 24.875 ;
        RECT 57.150 23.875 58.175 24.620 ;
        RECT 58.315 23.875 59.315 24.875 ;
        RECT 59.515 24.855 59.945 25.335 ;
        RECT 62.435 25.295 63.435 26.295 ;
        RECT 63.575 26.035 64.575 26.305 ;
        RECT 65.375 26.210 65.605 27.025 ;
        RECT 66.015 35.665 66.245 36.210 ;
        RECT 66.015 26.695 66.495 35.665 ;
        RECT 66.015 26.210 66.245 26.695 ;
        RECT 66.765 26.035 67.035 36.585 ;
        RECT 67.625 46.255 67.985 46.265 ;
        RECT 67.625 45.955 69.015 46.255 ;
        RECT 69.475 46.035 69.945 46.755 ;
        RECT 70.725 46.225 70.955 47.420 ;
        RECT 70.485 46.035 70.955 46.225 ;
        RECT 67.625 37.535 67.985 45.955 ;
        RECT 69.195 45.795 70.955 46.035 ;
        RECT 68.405 45.595 68.635 45.795 ;
        RECT 68.125 38.075 68.635 45.595 ;
        RECT 68.405 37.795 68.635 38.075 ;
        RECT 69.045 45.455 70.955 45.795 ;
        RECT 69.045 44.305 69.555 45.455 ;
        RECT 70.485 44.305 70.955 45.455 ;
        RECT 69.045 43.005 70.955 44.305 ;
        RECT 69.045 39.965 69.555 43.005 ;
        RECT 70.485 39.965 70.955 43.005 ;
        RECT 69.045 38.665 70.955 39.965 ;
        RECT 69.045 37.845 69.555 38.665 ;
        RECT 69.045 37.795 69.275 37.845 ;
        RECT 68.685 37.605 68.995 37.635 ;
        RECT 68.625 37.535 69.025 37.605 ;
        RECT 67.625 36.935 69.025 37.535 ;
        RECT 67.625 28.515 67.985 36.935 ;
        RECT 68.625 36.865 69.025 36.935 ;
        RECT 68.405 36.385 68.635 36.705 ;
        RECT 68.145 28.865 68.635 36.385 ;
        RECT 68.405 28.705 68.635 28.865 ;
        RECT 69.045 36.695 69.275 36.705 ;
        RECT 69.045 34.705 69.545 36.695 ;
        RECT 69.755 34.705 70.165 38.665 ;
        RECT 70.485 38.315 70.955 38.665 ;
        RECT 70.725 37.420 70.955 38.315 ;
        RECT 71.365 47.075 71.595 47.420 ;
        RECT 71.365 38.105 71.925 47.075 ;
        RECT 71.365 37.420 71.595 38.105 ;
        RECT 71.005 37.195 71.315 37.215 ;
        RECT 70.985 37.065 71.315 37.195 ;
        RECT 72.115 37.065 72.385 47.635 ;
        RECT 73.015 47.245 74.015 48.725 ;
        RECT 78.800 48.545 79.335 49.330 ;
        RECT 81.670 49.225 82.420 49.330 ;
        RECT 74.235 47.445 75.235 48.445 ;
        RECT 75.475 48.115 77.265 48.435 ;
        RECT 76.255 47.595 77.665 47.865 ;
        RECT 76.285 47.585 76.595 47.595 ;
        RECT 73.015 46.715 75.225 47.245 ;
        RECT 70.985 36.615 72.385 37.065 ;
        RECT 70.985 36.465 71.315 36.615 ;
        RECT 71.005 36.445 71.315 36.465 ;
        RECT 70.725 34.965 70.955 36.240 ;
        RECT 70.455 34.705 70.955 34.965 ;
        RECT 69.045 33.405 70.955 34.705 ;
        RECT 69.045 30.775 69.545 33.405 ;
        RECT 70.455 30.775 70.955 33.405 ;
        RECT 69.045 29.475 70.955 30.775 ;
        RECT 69.045 28.785 69.545 29.475 ;
        RECT 69.045 28.705 69.275 28.785 ;
        RECT 68.685 28.515 68.995 28.545 ;
        RECT 67.625 28.235 68.995 28.515 ;
        RECT 68.695 28.085 68.995 28.235 ;
        RECT 68.695 27.835 69.385 28.085 ;
        RECT 67.785 26.575 68.785 27.575 ;
        RECT 68.925 27.565 69.385 27.835 ;
        RECT 68.925 26.565 69.925 27.565 ;
        RECT 70.455 27.055 70.955 29.475 ;
        RECT 63.575 25.665 67.035 26.035 ;
        RECT 63.575 25.305 65.175 25.665 ;
        RECT 67.785 25.325 68.785 26.325 ;
        RECT 68.925 26.065 69.925 26.335 ;
        RECT 70.725 26.240 70.955 27.055 ;
        RECT 71.365 35.695 71.595 36.240 ;
        RECT 71.365 26.725 71.845 35.695 ;
        RECT 71.365 26.240 71.595 26.725 ;
        RECT 72.115 26.065 72.385 36.615 ;
        RECT 72.905 46.215 73.265 46.225 ;
        RECT 72.905 45.915 74.295 46.215 ;
        RECT 74.755 45.995 75.225 46.715 ;
        RECT 76.005 46.185 76.235 47.380 ;
        RECT 75.765 45.995 76.235 46.185 ;
        RECT 72.905 37.495 73.265 45.915 ;
        RECT 74.475 45.755 76.235 45.995 ;
        RECT 73.685 45.555 73.915 45.755 ;
        RECT 73.405 38.035 73.915 45.555 ;
        RECT 73.685 37.755 73.915 38.035 ;
        RECT 74.325 45.415 76.235 45.755 ;
        RECT 74.325 44.265 74.835 45.415 ;
        RECT 75.765 44.265 76.235 45.415 ;
        RECT 74.325 42.965 76.235 44.265 ;
        RECT 74.325 39.925 74.835 42.965 ;
        RECT 75.765 39.925 76.235 42.965 ;
        RECT 74.325 38.625 76.235 39.925 ;
        RECT 74.325 37.805 74.835 38.625 ;
        RECT 74.325 37.755 74.555 37.805 ;
        RECT 73.965 37.565 74.275 37.595 ;
        RECT 73.905 37.495 74.305 37.565 ;
        RECT 72.905 36.895 74.305 37.495 ;
        RECT 72.905 28.475 73.265 36.895 ;
        RECT 73.905 36.825 74.305 36.895 ;
        RECT 73.685 36.345 73.915 36.665 ;
        RECT 73.425 28.825 73.915 36.345 ;
        RECT 73.685 28.665 73.915 28.825 ;
        RECT 74.325 36.655 74.555 36.665 ;
        RECT 74.325 34.665 74.825 36.655 ;
        RECT 75.035 34.665 75.445 38.625 ;
        RECT 75.765 38.275 76.235 38.625 ;
        RECT 76.005 37.380 76.235 38.275 ;
        RECT 76.645 47.035 76.875 47.380 ;
        RECT 76.645 38.065 77.205 47.035 ;
        RECT 76.645 37.380 76.875 38.065 ;
        RECT 76.285 37.155 76.595 37.175 ;
        RECT 76.265 37.025 76.595 37.155 ;
        RECT 77.395 37.025 77.665 47.595 ;
        RECT 78.605 47.255 79.605 48.545 ;
        RECT 79.825 47.455 80.825 49.015 ;
        RECT 84.180 48.525 84.715 49.330 ;
        RECT 89.475 48.705 90.010 49.330 ;
        RECT 95.055 48.715 95.590 49.330 ;
        RECT 81.125 48.125 82.915 48.445 ;
        RECT 83.945 47.975 84.945 48.525 ;
        RECT 81.845 47.605 83.255 47.875 ;
        RECT 81.875 47.595 82.185 47.605 ;
        RECT 78.605 46.725 80.815 47.255 ;
        RECT 76.265 36.575 77.665 37.025 ;
        RECT 76.265 36.425 76.595 36.575 ;
        RECT 76.285 36.405 76.595 36.425 ;
        RECT 76.005 34.925 76.235 36.200 ;
        RECT 75.735 34.665 76.235 34.925 ;
        RECT 74.325 33.365 76.235 34.665 ;
        RECT 74.325 30.735 74.825 33.365 ;
        RECT 75.735 30.735 76.235 33.365 ;
        RECT 74.325 29.435 76.235 30.735 ;
        RECT 74.325 28.745 74.825 29.435 ;
        RECT 74.325 28.665 74.555 28.745 ;
        RECT 73.965 28.475 74.275 28.505 ;
        RECT 72.905 28.195 74.275 28.475 ;
        RECT 73.975 28.045 74.275 28.195 ;
        RECT 73.975 27.795 74.665 28.045 ;
        RECT 73.065 26.535 74.065 27.535 ;
        RECT 74.205 27.525 74.665 27.795 ;
        RECT 74.205 26.525 75.205 27.525 ;
        RECT 75.735 27.015 76.235 29.435 ;
        RECT 68.925 25.695 72.385 26.065 ;
        RECT 68.925 25.345 70.585 25.695 ;
        RECT 68.925 25.335 69.925 25.345 ;
        RECT 62.775 24.885 63.435 25.295 ;
        RECT 57.150 17.840 58.140 23.875 ;
        RECT 59.505 23.855 60.505 24.855 ;
        RECT 61.085 23.875 62.085 24.875 ;
        RECT 62.455 23.885 63.455 24.885 ;
        RECT 59.900 22.705 60.135 23.855 ;
        RECT 59.885 22.385 60.145 22.705 ;
        RECT 62.460 17.840 63.320 23.885 ;
        RECT 63.615 23.875 64.615 24.875 ;
        RECT 64.785 24.865 65.175 25.305 ;
        RECT 67.935 24.905 68.665 25.325 ;
        RECT 63.950 21.710 64.220 23.875 ;
        RECT 64.785 23.865 65.785 24.865 ;
        RECT 67.675 24.470 68.675 24.905 ;
        RECT 70.145 24.895 70.585 25.345 ;
        RECT 73.065 25.285 74.065 26.285 ;
        RECT 74.205 26.025 75.205 26.295 ;
        RECT 76.005 26.200 76.235 27.015 ;
        RECT 76.645 35.655 76.875 36.200 ;
        RECT 76.645 26.685 77.125 35.655 ;
        RECT 76.645 26.200 76.875 26.685 ;
        RECT 77.395 26.025 77.665 36.575 ;
        RECT 78.495 46.225 78.855 46.235 ;
        RECT 78.495 45.925 79.885 46.225 ;
        RECT 80.345 46.005 80.815 46.725 ;
        RECT 81.595 46.195 81.825 47.390 ;
        RECT 81.355 46.005 81.825 46.195 ;
        RECT 78.495 37.505 78.855 45.925 ;
        RECT 80.065 45.765 81.825 46.005 ;
        RECT 79.275 45.565 79.505 45.765 ;
        RECT 78.995 38.045 79.505 45.565 ;
        RECT 79.275 37.765 79.505 38.045 ;
        RECT 79.915 45.425 81.825 45.765 ;
        RECT 79.915 44.275 80.425 45.425 ;
        RECT 81.355 44.275 81.825 45.425 ;
        RECT 79.915 42.975 81.825 44.275 ;
        RECT 79.915 39.935 80.425 42.975 ;
        RECT 81.355 39.935 81.825 42.975 ;
        RECT 79.915 38.635 81.825 39.935 ;
        RECT 79.915 37.815 80.425 38.635 ;
        RECT 79.915 37.765 80.145 37.815 ;
        RECT 79.555 37.575 79.865 37.605 ;
        RECT 79.495 37.505 79.895 37.575 ;
        RECT 78.495 36.905 79.895 37.505 ;
        RECT 78.495 28.485 78.855 36.905 ;
        RECT 79.495 36.835 79.895 36.905 ;
        RECT 79.275 36.355 79.505 36.675 ;
        RECT 79.015 28.835 79.505 36.355 ;
        RECT 79.275 28.675 79.505 28.835 ;
        RECT 79.915 36.665 80.145 36.675 ;
        RECT 79.915 34.675 80.415 36.665 ;
        RECT 80.625 34.675 81.035 38.635 ;
        RECT 81.355 38.285 81.825 38.635 ;
        RECT 81.595 37.390 81.825 38.285 ;
        RECT 82.235 47.045 82.465 47.390 ;
        RECT 82.235 38.075 82.795 47.045 ;
        RECT 82.235 37.390 82.465 38.075 ;
        RECT 81.875 37.165 82.185 37.185 ;
        RECT 81.855 37.035 82.185 37.165 ;
        RECT 82.985 37.035 83.255 47.605 ;
        RECT 83.945 47.525 84.955 47.975 ;
        RECT 83.955 47.245 84.955 47.525 ;
        RECT 85.175 47.445 86.175 48.445 ;
        RECT 86.515 48.105 88.305 48.425 ;
        RECT 89.295 48.005 90.295 48.705 ;
        RECT 87.195 47.595 88.605 47.865 ;
        RECT 89.295 47.705 90.305 48.005 ;
        RECT 87.225 47.585 87.535 47.595 ;
        RECT 85.255 47.435 86.135 47.445 ;
        RECT 83.955 46.715 86.165 47.245 ;
        RECT 81.855 36.585 83.255 37.035 ;
        RECT 81.855 36.435 82.185 36.585 ;
        RECT 81.875 36.415 82.185 36.435 ;
        RECT 81.595 34.935 81.825 36.210 ;
        RECT 81.325 34.675 81.825 34.935 ;
        RECT 79.915 33.375 81.825 34.675 ;
        RECT 79.915 30.745 80.415 33.375 ;
        RECT 81.325 30.745 81.825 33.375 ;
        RECT 79.915 29.445 81.825 30.745 ;
        RECT 79.915 28.755 80.415 29.445 ;
        RECT 79.915 28.675 80.145 28.755 ;
        RECT 79.555 28.485 79.865 28.515 ;
        RECT 78.495 28.205 79.865 28.485 ;
        RECT 79.565 28.055 79.865 28.205 ;
        RECT 79.565 27.805 80.255 28.055 ;
        RECT 78.655 26.545 79.655 27.545 ;
        RECT 79.795 27.535 80.255 27.805 ;
        RECT 79.795 26.535 80.795 27.535 ;
        RECT 81.325 27.025 81.825 29.445 ;
        RECT 74.205 25.655 77.665 26.025 ;
        RECT 74.205 25.295 75.815 25.655 ;
        RECT 78.655 25.295 79.655 26.295 ;
        RECT 79.795 26.035 80.795 26.305 ;
        RECT 81.595 26.210 81.825 27.025 ;
        RECT 82.235 35.665 82.465 36.210 ;
        RECT 82.235 26.695 82.715 35.665 ;
        RECT 82.235 26.210 82.465 26.695 ;
        RECT 82.985 26.035 83.255 36.585 ;
        RECT 83.845 46.215 84.205 46.225 ;
        RECT 83.845 45.915 85.235 46.215 ;
        RECT 85.695 45.995 86.165 46.715 ;
        RECT 86.945 46.185 87.175 47.380 ;
        RECT 86.705 45.995 87.175 46.185 ;
        RECT 83.845 37.495 84.205 45.915 ;
        RECT 85.415 45.755 87.175 45.995 ;
        RECT 84.625 45.555 84.855 45.755 ;
        RECT 84.345 38.035 84.855 45.555 ;
        RECT 84.625 37.755 84.855 38.035 ;
        RECT 85.265 45.415 87.175 45.755 ;
        RECT 85.265 44.265 85.775 45.415 ;
        RECT 86.705 44.265 87.175 45.415 ;
        RECT 85.265 42.965 87.175 44.265 ;
        RECT 85.265 39.925 85.775 42.965 ;
        RECT 86.705 39.925 87.175 42.965 ;
        RECT 85.265 38.625 87.175 39.925 ;
        RECT 85.265 37.805 85.775 38.625 ;
        RECT 85.265 37.755 85.495 37.805 ;
        RECT 84.905 37.565 85.215 37.595 ;
        RECT 84.845 37.495 85.245 37.565 ;
        RECT 83.845 36.895 85.245 37.495 ;
        RECT 83.845 28.475 84.205 36.895 ;
        RECT 84.845 36.825 85.245 36.895 ;
        RECT 84.625 36.345 84.855 36.665 ;
        RECT 84.365 28.825 84.855 36.345 ;
        RECT 84.625 28.665 84.855 28.825 ;
        RECT 85.265 36.655 85.495 36.665 ;
        RECT 85.265 34.665 85.765 36.655 ;
        RECT 85.975 34.665 86.385 38.625 ;
        RECT 86.705 38.275 87.175 38.625 ;
        RECT 86.945 37.380 87.175 38.275 ;
        RECT 87.585 47.035 87.815 47.380 ;
        RECT 87.585 38.065 88.145 47.035 ;
        RECT 87.585 37.380 87.815 38.065 ;
        RECT 87.225 37.155 87.535 37.175 ;
        RECT 87.205 37.025 87.535 37.155 ;
        RECT 88.335 37.025 88.605 47.595 ;
        RECT 89.305 47.275 90.305 47.705 ;
        RECT 90.525 47.475 91.525 48.475 ;
        RECT 91.865 48.145 93.655 48.465 ;
        RECT 94.585 48.150 95.590 48.715 ;
        RECT 92.545 47.625 93.955 47.895 ;
        RECT 92.575 47.615 92.885 47.625 ;
        RECT 90.595 47.465 91.475 47.475 ;
        RECT 89.305 46.745 91.515 47.275 ;
        RECT 87.205 36.575 88.605 37.025 ;
        RECT 87.205 36.425 87.535 36.575 ;
        RECT 87.225 36.405 87.535 36.425 ;
        RECT 86.945 34.925 87.175 36.200 ;
        RECT 86.675 34.665 87.175 34.925 ;
        RECT 85.265 33.365 87.175 34.665 ;
        RECT 85.265 30.735 85.765 33.365 ;
        RECT 86.675 30.735 87.175 33.365 ;
        RECT 85.265 29.435 87.175 30.735 ;
        RECT 85.265 28.745 85.765 29.435 ;
        RECT 85.265 28.665 85.495 28.745 ;
        RECT 84.905 28.475 85.215 28.505 ;
        RECT 83.845 28.195 85.215 28.475 ;
        RECT 84.915 28.045 85.215 28.195 ;
        RECT 84.915 27.795 85.605 28.045 ;
        RECT 84.005 26.535 85.005 27.535 ;
        RECT 85.145 27.525 85.605 27.795 ;
        RECT 85.145 26.525 86.145 27.525 ;
        RECT 86.675 27.015 87.175 29.435 ;
        RECT 79.795 25.665 83.255 26.035 ;
        RECT 79.795 25.325 81.515 25.665 ;
        RECT 79.795 25.305 80.795 25.325 ;
        RECT 67.640 23.905 68.675 24.470 ;
        RECT 63.955 21.685 64.215 21.710 ;
        RECT 65.160 21.100 65.450 23.865 ;
        RECT 65.175 21.085 65.435 21.100 ;
        RECT 67.640 18.200 68.650 23.905 ;
        RECT 68.845 23.895 69.845 24.895 ;
        RECT 70.015 23.895 71.015 24.895 ;
        RECT 73.065 24.835 73.825 25.285 ;
        RECT 75.195 24.835 75.815 25.295 ;
        RECT 78.975 24.865 79.585 25.295 ;
        RECT 69.160 20.405 69.495 23.895 ;
        RECT 70.290 19.860 70.680 23.895 ;
        RECT 72.825 23.835 73.825 24.835 ;
        RECT 73.965 23.835 74.965 24.835 ;
        RECT 75.185 23.835 76.185 24.835 ;
        RECT 78.745 24.210 79.745 24.865 ;
        RECT 78.660 23.865 79.745 24.210 ;
        RECT 79.885 23.865 80.885 24.865 ;
        RECT 81.085 24.845 81.515 25.325 ;
        RECT 84.005 25.285 85.005 26.285 ;
        RECT 85.145 26.025 86.145 26.295 ;
        RECT 86.945 26.200 87.175 27.015 ;
        RECT 87.585 35.655 87.815 36.200 ;
        RECT 87.585 26.685 88.065 35.655 ;
        RECT 87.585 26.200 87.815 26.685 ;
        RECT 88.335 26.025 88.605 36.575 ;
        RECT 89.195 46.245 89.555 46.255 ;
        RECT 89.195 45.945 90.585 46.245 ;
        RECT 91.045 46.025 91.515 46.745 ;
        RECT 92.295 46.215 92.525 47.410 ;
        RECT 92.055 46.025 92.525 46.215 ;
        RECT 89.195 37.525 89.555 45.945 ;
        RECT 90.765 45.785 92.525 46.025 ;
        RECT 89.975 45.585 90.205 45.785 ;
        RECT 89.695 38.065 90.205 45.585 ;
        RECT 89.975 37.785 90.205 38.065 ;
        RECT 90.615 45.445 92.525 45.785 ;
        RECT 90.615 44.295 91.125 45.445 ;
        RECT 92.055 44.295 92.525 45.445 ;
        RECT 90.615 42.995 92.525 44.295 ;
        RECT 90.615 39.955 91.125 42.995 ;
        RECT 92.055 39.955 92.525 42.995 ;
        RECT 90.615 38.655 92.525 39.955 ;
        RECT 90.615 37.835 91.125 38.655 ;
        RECT 90.615 37.785 90.845 37.835 ;
        RECT 90.255 37.595 90.565 37.625 ;
        RECT 90.195 37.525 90.595 37.595 ;
        RECT 89.195 36.925 90.595 37.525 ;
        RECT 89.195 28.505 89.555 36.925 ;
        RECT 90.195 36.855 90.595 36.925 ;
        RECT 89.975 36.375 90.205 36.695 ;
        RECT 89.715 28.855 90.205 36.375 ;
        RECT 89.975 28.695 90.205 28.855 ;
        RECT 90.615 36.685 90.845 36.695 ;
        RECT 90.615 34.695 91.115 36.685 ;
        RECT 91.325 34.695 91.735 38.655 ;
        RECT 92.055 38.305 92.525 38.655 ;
        RECT 92.295 37.410 92.525 38.305 ;
        RECT 92.935 47.065 93.165 47.410 ;
        RECT 92.935 38.095 93.495 47.065 ;
        RECT 92.935 37.410 93.165 38.095 ;
        RECT 92.575 37.185 92.885 37.205 ;
        RECT 92.555 37.055 92.885 37.185 ;
        RECT 93.685 37.055 93.955 47.625 ;
        RECT 94.585 47.235 95.585 48.150 ;
        RECT 95.805 47.435 96.805 48.435 ;
        RECT 97.045 48.105 98.835 48.425 ;
        RECT 97.825 47.585 99.235 47.855 ;
        RECT 97.855 47.575 98.165 47.585 ;
        RECT 94.585 46.705 96.795 47.235 ;
        RECT 92.555 36.605 93.955 37.055 ;
        RECT 92.555 36.455 92.885 36.605 ;
        RECT 92.575 36.435 92.885 36.455 ;
        RECT 92.295 34.955 92.525 36.230 ;
        RECT 92.025 34.695 92.525 34.955 ;
        RECT 90.615 33.395 92.525 34.695 ;
        RECT 90.615 30.765 91.115 33.395 ;
        RECT 92.025 30.765 92.525 33.395 ;
        RECT 90.615 29.465 92.525 30.765 ;
        RECT 90.615 28.775 91.115 29.465 ;
        RECT 90.615 28.695 90.845 28.775 ;
        RECT 90.255 28.505 90.565 28.535 ;
        RECT 89.195 28.225 90.565 28.505 ;
        RECT 90.265 28.075 90.565 28.225 ;
        RECT 90.265 27.825 90.955 28.075 ;
        RECT 89.355 26.565 90.355 27.565 ;
        RECT 90.495 27.555 90.955 27.825 ;
        RECT 90.495 26.555 91.495 27.555 ;
        RECT 92.025 27.045 92.525 29.465 ;
        RECT 85.145 25.655 88.605 26.025 ;
        RECT 85.145 25.295 86.745 25.655 ;
        RECT 89.355 25.315 90.355 26.315 ;
        RECT 90.495 26.055 91.495 26.325 ;
        RECT 92.295 26.230 92.525 27.045 ;
        RECT 92.935 35.685 93.165 36.230 ;
        RECT 92.935 26.715 93.415 35.685 ;
        RECT 92.935 26.230 93.165 26.715 ;
        RECT 93.685 26.055 93.955 36.605 ;
        RECT 94.475 46.205 94.835 46.215 ;
        RECT 94.475 45.905 95.865 46.205 ;
        RECT 96.325 45.985 96.795 46.705 ;
        RECT 97.575 46.175 97.805 47.370 ;
        RECT 97.335 45.985 97.805 46.175 ;
        RECT 94.475 37.485 94.835 45.905 ;
        RECT 96.045 45.745 97.805 45.985 ;
        RECT 95.255 45.545 95.485 45.745 ;
        RECT 94.975 38.025 95.485 45.545 ;
        RECT 95.255 37.745 95.485 38.025 ;
        RECT 95.895 45.405 97.805 45.745 ;
        RECT 95.895 44.255 96.405 45.405 ;
        RECT 97.335 44.255 97.805 45.405 ;
        RECT 95.895 42.955 97.805 44.255 ;
        RECT 95.895 39.915 96.405 42.955 ;
        RECT 97.335 39.915 97.805 42.955 ;
        RECT 95.895 38.615 97.805 39.915 ;
        RECT 95.895 37.795 96.405 38.615 ;
        RECT 95.895 37.745 96.125 37.795 ;
        RECT 95.535 37.555 95.845 37.585 ;
        RECT 95.475 37.485 95.875 37.555 ;
        RECT 94.475 36.885 95.875 37.485 ;
        RECT 94.475 28.465 94.835 36.885 ;
        RECT 95.475 36.815 95.875 36.885 ;
        RECT 95.255 36.335 95.485 36.655 ;
        RECT 94.995 28.815 95.485 36.335 ;
        RECT 95.255 28.655 95.485 28.815 ;
        RECT 95.895 36.645 96.125 36.655 ;
        RECT 95.895 34.655 96.395 36.645 ;
        RECT 96.605 34.655 97.015 38.615 ;
        RECT 97.335 38.265 97.805 38.615 ;
        RECT 97.575 37.370 97.805 38.265 ;
        RECT 98.215 47.025 98.445 47.370 ;
        RECT 98.215 38.055 98.775 47.025 ;
        RECT 98.215 37.370 98.445 38.055 ;
        RECT 97.855 37.145 98.165 37.165 ;
        RECT 97.835 37.015 98.165 37.145 ;
        RECT 98.965 37.015 99.235 47.585 ;
        RECT 97.835 36.565 99.235 37.015 ;
        RECT 97.835 36.415 98.165 36.565 ;
        RECT 97.855 36.395 98.165 36.415 ;
        RECT 97.575 34.915 97.805 36.190 ;
        RECT 97.305 34.655 97.805 34.915 ;
        RECT 95.895 33.355 97.805 34.655 ;
        RECT 95.895 30.725 96.395 33.355 ;
        RECT 97.305 30.725 97.805 33.355 ;
        RECT 95.895 29.425 97.805 30.725 ;
        RECT 95.895 28.735 96.395 29.425 ;
        RECT 95.895 28.655 96.125 28.735 ;
        RECT 95.535 28.465 95.845 28.495 ;
        RECT 94.475 28.185 95.845 28.465 ;
        RECT 95.545 28.035 95.845 28.185 ;
        RECT 95.545 27.785 96.235 28.035 ;
        RECT 94.635 26.525 95.635 27.525 ;
        RECT 95.775 27.515 96.235 27.785 ;
        RECT 95.775 26.515 96.775 27.515 ;
        RECT 97.305 27.005 97.805 29.425 ;
        RECT 90.495 25.685 93.955 26.055 ;
        RECT 90.495 25.335 92.155 25.685 ;
        RECT 90.495 25.325 91.495 25.335 ;
        RECT 84.345 24.875 85.005 25.285 ;
        RECT 72.900 18.520 73.740 23.835 ;
        RECT 74.350 19.235 74.785 23.835 ;
        RECT 75.530 18.635 76.035 23.835 ;
        RECT 78.660 19.400 79.560 23.865 ;
        RECT 81.075 23.845 82.075 24.845 ;
        RECT 82.655 23.865 83.655 24.865 ;
        RECT 84.025 23.875 85.025 24.875 ;
        RECT 84.050 20.330 84.950 23.875 ;
        RECT 85.185 23.865 86.185 24.865 ;
        RECT 86.355 24.855 86.745 25.295 ;
        RECT 89.505 24.895 90.235 25.315 ;
        RECT 86.355 23.855 87.355 24.855 ;
        RECT 89.245 24.530 90.245 24.895 ;
        RECT 91.715 24.885 92.155 25.335 ;
        RECT 94.635 25.275 95.635 26.275 ;
        RECT 95.775 26.015 96.775 26.285 ;
        RECT 97.575 26.190 97.805 27.005 ;
        RECT 98.215 35.645 98.445 36.190 ;
        RECT 98.215 26.675 98.695 35.645 ;
        RECT 98.215 26.190 98.445 26.675 ;
        RECT 98.965 26.015 99.235 36.565 ;
        RECT 95.775 25.645 99.235 26.015 ;
        RECT 95.775 25.285 97.385 25.645 ;
        RECT 89.150 23.895 90.245 24.530 ;
        RECT 89.150 21.610 90.140 23.895 ;
        RECT 90.415 23.885 91.415 24.885 ;
        RECT 91.585 23.885 92.585 24.885 ;
        RECT 94.635 24.825 95.395 25.275 ;
        RECT 96.765 24.825 97.385 25.285 ;
        RECT 94.395 23.825 95.395 24.825 ;
        RECT 95.535 23.825 96.535 24.825 ;
        RECT 96.755 23.825 97.755 24.825 ;
        RECT 94.460 22.880 95.300 23.825 ;
        RECT 137.870 22.880 139.520 22.920 ;
        RECT 94.390 22.350 139.520 22.880 ;
        RECT 94.460 22.330 95.300 22.350 ;
        RECT 137.870 21.830 139.520 22.350 ;
        RECT 89.150 21.140 126.310 21.610 ;
        RECT 89.150 21.100 90.140 21.140 ;
        RECT 124.790 20.780 126.240 21.140 ;
        RECT 84.050 20.320 112.490 20.330 ;
        RECT 84.050 20.000 112.660 20.320 ;
        RECT 84.050 19.970 84.950 20.000 ;
        RECT 98.610 19.400 99.670 19.440 ;
        RECT 111.250 19.400 112.660 20.000 ;
        RECT 78.660 19.070 99.670 19.400 ;
        RECT 78.660 19.040 79.560 19.070 ;
        RECT 98.610 18.930 99.670 19.070 ;
        RECT 72.900 18.480 75.340 18.520 ;
        RECT 76.210 18.480 86.520 18.520 ;
        RECT 72.900 18.270 86.520 18.480 ;
        RECT 75.250 18.260 76.570 18.270 ;
        RECT 46.650 17.700 58.140 17.840 ;
        RECT 46.650 17.320 58.090 17.700 ;
        RECT 46.690 13.890 47.590 17.320 ;
        RECT 62.350 17.030 63.400 17.840 ;
        RECT 67.530 17.710 68.690 18.200 ;
        RECT 85.340 17.790 86.520 18.270 ;
        RECT 46.690 13.430 47.700 13.890 ;
        RECT 59.610 13.750 60.610 13.790 ;
        RECT 46.700 13.040 47.700 13.430 ;
        RECT 59.580 13.060 60.730 13.750 ;
        RECT 72.460 13.130 73.800 13.980 ;
        RECT 46.620 12.060 48.170 13.040 ;
        RECT 45.680 12.050 48.170 12.060 ;
        RECT 48.700 12.050 49.010 12.090 ;
        RECT 59.470 12.080 61.020 13.060 ;
        RECT 72.460 13.020 74.030 13.130 ;
        RECT 85.480 13.060 86.660 13.840 ;
        RECT 72.480 12.150 74.030 13.020 ;
        RECT 71.540 12.140 74.030 12.150 ;
        RECT 74.560 12.140 74.870 12.180 ;
        RECT 71.540 12.130 74.870 12.140 ;
        RECT 58.530 12.070 61.020 12.080 ;
        RECT 61.550 12.070 61.860 12.110 ;
        RECT 58.530 12.060 61.860 12.070 ;
        RECT 45.680 12.040 49.010 12.050 ;
        RECT 45.600 11.910 49.010 12.040 ;
        RECT 50.660 11.970 51.550 11.980 ;
        RECT 45.600 11.770 46.760 11.910 ;
        RECT 48.700 11.820 49.010 11.910 ;
        RECT 50.640 11.830 51.550 11.970 ;
        RECT 58.450 11.930 61.860 12.060 ;
        RECT 71.460 12.000 74.870 12.130 ;
        RECT 85.330 12.080 86.880 13.060 ;
        RECT 98.620 13.010 99.960 13.660 ;
        RECT 84.390 12.070 86.880 12.080 ;
        RECT 87.410 12.070 87.720 12.110 ;
        RECT 76.520 12.060 77.410 12.070 ;
        RECT 84.390 12.060 87.720 12.070 ;
        RECT 63.510 11.990 64.400 12.000 ;
        RECT 45.600 11.720 46.630 11.770 ;
        RECT 45.630 11.630 46.630 11.720 ;
        RECT 50.640 11.680 51.500 11.830 ;
        RECT 58.450 11.790 59.610 11.930 ;
        RECT 61.550 11.840 61.860 11.930 ;
        RECT 63.490 11.850 64.400 11.990 ;
        RECT 71.460 11.860 72.620 12.000 ;
        RECT 74.560 11.910 74.870 12.000 ;
        RECT 76.500 11.920 77.410 12.060 ;
        RECT 84.310 11.930 87.720 12.060 ;
        RECT 98.450 12.030 100.000 13.010 ;
        RECT 111.470 12.960 112.700 13.550 ;
        RECT 97.510 12.020 100.000 12.030 ;
        RECT 100.530 12.020 100.840 12.060 ;
        RECT 97.510 12.010 100.840 12.020 ;
        RECT 89.370 11.990 90.260 12.000 ;
        RECT 58.450 11.740 59.480 11.790 ;
        RECT 48.470 11.430 48.700 11.680 ;
        RECT 48.000 11.290 48.700 11.430 ;
        RECT 47.850 10.820 48.700 11.290 ;
        RECT 50.640 11.330 50.960 11.680 ;
        RECT 58.480 11.650 59.480 11.740 ;
        RECT 63.490 11.700 64.350 11.850 ;
        RECT 71.460 11.810 72.490 11.860 ;
        RECT 71.490 11.720 72.490 11.810 ;
        RECT 76.500 11.770 77.360 11.920 ;
        RECT 84.310 11.790 85.470 11.930 ;
        RECT 87.410 11.840 87.720 11.930 ;
        RECT 89.350 11.850 90.260 11.990 ;
        RECT 97.430 11.880 100.840 12.010 ;
        RECT 111.350 11.980 112.900 12.960 ;
        RECT 125.110 12.920 126.440 13.640 ;
        RECT 138.180 12.920 139.500 13.670 ;
        RECT 110.410 11.970 112.900 11.980 ;
        RECT 113.430 11.970 113.740 12.010 ;
        RECT 110.410 11.960 113.740 11.970 ;
        RECT 102.490 11.940 103.380 11.950 ;
        RECT 61.320 11.450 61.550 11.700 ;
        RECT 50.640 11.000 50.970 11.330 ;
        RECT 60.850 11.310 61.550 11.450 ;
        RECT 45.630 10.340 46.630 10.570 ;
        RECT 45.690 9.600 46.580 10.340 ;
        RECT 45.570 9.380 46.580 9.600 ;
        RECT 45.510 9.360 46.790 9.380 ;
        RECT 47.850 9.360 48.120 10.820 ;
        RECT 48.470 10.680 48.700 10.820 ;
        RECT 48.700 10.270 49.010 10.540 ;
        RECT 48.760 10.030 48.990 10.270 ;
        RECT 50.660 10.030 50.970 11.000 ;
        RECT 60.700 10.840 61.550 11.310 ;
        RECT 63.490 11.350 63.810 11.700 ;
        RECT 74.330 11.520 74.560 11.770 ;
        RECT 73.860 11.380 74.560 11.520 ;
        RECT 63.490 11.020 63.820 11.350 ;
        RECT 58.480 10.360 59.480 10.590 ;
        RECT 48.760 9.900 50.970 10.030 ;
        RECT 48.760 9.890 50.960 9.900 ;
        RECT 48.760 9.880 48.990 9.890 ;
        RECT 58.540 9.620 59.430 10.360 ;
        RECT 58.420 9.400 59.430 9.620 ;
        RECT 45.510 9.130 48.120 9.360 ;
        RECT 45.230 9.100 48.120 9.130 ;
        RECT 58.360 9.380 59.640 9.400 ;
        RECT 60.700 9.380 60.970 10.840 ;
        RECT 61.320 10.700 61.550 10.840 ;
        RECT 61.550 10.290 61.860 10.560 ;
        RECT 61.610 10.050 61.840 10.290 ;
        RECT 63.510 10.050 63.820 11.020 ;
        RECT 73.710 10.910 74.560 11.380 ;
        RECT 76.500 11.420 76.820 11.770 ;
        RECT 84.310 11.740 85.340 11.790 ;
        RECT 84.340 11.650 85.340 11.740 ;
        RECT 89.350 11.700 90.210 11.850 ;
        RECT 97.430 11.740 98.590 11.880 ;
        RECT 100.530 11.790 100.840 11.880 ;
        RECT 102.470 11.800 103.380 11.940 ;
        RECT 110.330 11.830 113.740 11.960 ;
        RECT 125.090 11.940 126.640 12.920 ;
        RECT 124.150 11.930 126.640 11.940 ;
        RECT 127.170 11.930 127.480 11.970 ;
        RECT 138.180 11.940 139.730 12.920 ;
        RECT 124.150 11.920 127.480 11.930 ;
        RECT 137.240 11.930 139.730 11.940 ;
        RECT 140.260 11.930 140.570 11.970 ;
        RECT 137.240 11.920 140.570 11.930 ;
        RECT 115.390 11.890 116.280 11.900 ;
        RECT 87.180 11.450 87.410 11.700 ;
        RECT 76.500 11.090 76.830 11.420 ;
        RECT 86.710 11.310 87.410 11.450 ;
        RECT 71.490 10.430 72.490 10.660 ;
        RECT 61.610 9.920 63.820 10.050 ;
        RECT 61.610 9.910 63.810 9.920 ;
        RECT 61.610 9.900 61.840 9.910 ;
        RECT 71.550 9.690 72.440 10.430 ;
        RECT 71.430 9.470 72.440 9.690 ;
        RECT 58.360 9.120 60.970 9.380 ;
        RECT 71.370 9.450 72.650 9.470 ;
        RECT 73.710 9.450 73.980 10.910 ;
        RECT 74.330 10.770 74.560 10.910 ;
        RECT 74.560 10.360 74.870 10.630 ;
        RECT 74.620 10.120 74.850 10.360 ;
        RECT 76.520 10.120 76.830 11.090 ;
        RECT 86.560 10.840 87.410 11.310 ;
        RECT 89.350 11.350 89.670 11.700 ;
        RECT 97.430 11.690 98.460 11.740 ;
        RECT 97.460 11.600 98.460 11.690 ;
        RECT 102.470 11.650 103.330 11.800 ;
        RECT 110.330 11.690 111.490 11.830 ;
        RECT 113.430 11.740 113.740 11.830 ;
        RECT 115.370 11.750 116.280 11.890 ;
        RECT 124.070 11.790 127.480 11.920 ;
        RECT 129.130 11.850 130.020 11.860 ;
        RECT 100.300 11.400 100.530 11.650 ;
        RECT 89.350 11.020 89.680 11.350 ;
        RECT 99.830 11.260 100.530 11.400 ;
        RECT 84.340 10.360 85.340 10.590 ;
        RECT 74.620 9.990 76.830 10.120 ;
        RECT 74.620 9.980 76.820 9.990 ;
        RECT 74.620 9.970 74.850 9.980 ;
        RECT 84.400 9.620 85.290 10.360 ;
        RECT 71.370 9.190 73.980 9.450 ;
        RECT 84.280 9.400 85.290 9.620 ;
        RECT 84.220 9.380 85.500 9.400 ;
        RECT 86.560 9.380 86.830 10.840 ;
        RECT 87.180 10.700 87.410 10.840 ;
        RECT 87.410 10.290 87.720 10.560 ;
        RECT 87.470 10.050 87.700 10.290 ;
        RECT 89.370 10.050 89.680 11.020 ;
        RECT 99.680 10.790 100.530 11.260 ;
        RECT 102.470 11.300 102.790 11.650 ;
        RECT 110.330 11.640 111.360 11.690 ;
        RECT 110.360 11.550 111.360 11.640 ;
        RECT 115.370 11.600 116.230 11.750 ;
        RECT 124.070 11.650 125.230 11.790 ;
        RECT 127.170 11.700 127.480 11.790 ;
        RECT 129.110 11.710 130.020 11.850 ;
        RECT 137.160 11.790 140.570 11.920 ;
        RECT 142.220 11.850 143.110 11.860 ;
        RECT 124.070 11.600 125.100 11.650 ;
        RECT 113.200 11.350 113.430 11.600 ;
        RECT 102.470 10.970 102.800 11.300 ;
        RECT 112.730 11.210 113.430 11.350 ;
        RECT 97.460 10.310 98.460 10.540 ;
        RECT 87.470 9.920 89.680 10.050 ;
        RECT 87.470 9.910 89.670 9.920 ;
        RECT 87.470 9.900 87.700 9.910 ;
        RECT 97.520 9.570 98.410 10.310 ;
        RECT 71.370 9.120 72.650 9.190 ;
        RECT 45.230 8.930 46.790 9.100 ;
        RECT 58.360 9.050 59.640 9.120 ;
        RECT 58.190 8.950 59.640 9.050 ;
        RECT 71.200 9.020 72.650 9.120 ;
        RECT 84.220 9.120 86.830 9.380 ;
        RECT 97.400 9.350 98.410 9.570 ;
        RECT 97.340 9.330 98.620 9.350 ;
        RECT 99.680 9.330 99.950 10.790 ;
        RECT 100.300 10.650 100.530 10.790 ;
        RECT 100.530 10.240 100.840 10.510 ;
        RECT 100.590 10.000 100.820 10.240 ;
        RECT 102.490 10.000 102.800 10.970 ;
        RECT 112.580 10.740 113.430 11.210 ;
        RECT 115.370 11.250 115.690 11.600 ;
        RECT 124.100 11.510 125.100 11.600 ;
        RECT 129.110 11.560 129.970 11.710 ;
        RECT 137.160 11.650 138.320 11.790 ;
        RECT 140.260 11.700 140.570 11.790 ;
        RECT 142.200 11.710 143.110 11.850 ;
        RECT 137.160 11.600 138.190 11.650 ;
        RECT 126.940 11.310 127.170 11.560 ;
        RECT 115.370 10.920 115.700 11.250 ;
        RECT 126.470 11.170 127.170 11.310 ;
        RECT 110.360 10.260 111.360 10.490 ;
        RECT 100.590 9.870 102.800 10.000 ;
        RECT 100.590 9.860 102.790 9.870 ;
        RECT 100.590 9.850 100.820 9.860 ;
        RECT 110.420 9.520 111.310 10.260 ;
        RECT 84.220 9.050 85.500 9.120 ;
        RECT 45.230 8.310 46.770 8.930 ;
        RECT 58.190 8.620 59.420 8.950 ;
        RECT 71.200 8.690 72.430 9.020 ;
        RECT 84.050 8.950 85.500 9.050 ;
        RECT 97.340 9.070 99.950 9.330 ;
        RECT 110.300 9.300 111.310 9.520 ;
        RECT 110.240 9.280 111.520 9.300 ;
        RECT 112.580 9.280 112.850 10.740 ;
        RECT 113.200 10.600 113.430 10.740 ;
        RECT 113.430 10.190 113.740 10.460 ;
        RECT 113.490 9.950 113.720 10.190 ;
        RECT 115.390 9.950 115.700 10.920 ;
        RECT 126.320 10.700 127.170 11.170 ;
        RECT 129.110 11.210 129.430 11.560 ;
        RECT 137.190 11.510 138.190 11.600 ;
        RECT 142.200 11.560 143.060 11.710 ;
        RECT 140.030 11.310 140.260 11.560 ;
        RECT 129.110 10.880 129.440 11.210 ;
        RECT 139.560 11.170 140.260 11.310 ;
        RECT 124.100 10.220 125.100 10.450 ;
        RECT 113.490 9.820 115.700 9.950 ;
        RECT 113.490 9.810 115.690 9.820 ;
        RECT 113.490 9.800 113.720 9.810 ;
        RECT 124.160 9.480 125.050 10.220 ;
        RECT 97.340 9.000 98.620 9.070 ;
        RECT 58.190 8.390 59.380 8.620 ;
        RECT 71.200 8.460 72.390 8.690 ;
        RECT 84.050 8.620 85.280 8.950 ;
        RECT 97.170 8.900 98.620 9.000 ;
        RECT 110.240 9.020 112.850 9.280 ;
        RECT 124.040 9.260 125.050 9.480 ;
        RECT 123.980 9.240 125.260 9.260 ;
        RECT 126.320 9.240 126.590 10.700 ;
        RECT 126.940 10.560 127.170 10.700 ;
        RECT 127.170 10.150 127.480 10.420 ;
        RECT 127.230 9.910 127.460 10.150 ;
        RECT 129.130 9.910 129.440 10.880 ;
        RECT 139.410 10.700 140.260 11.170 ;
        RECT 142.200 11.210 142.520 11.560 ;
        RECT 142.200 10.880 142.530 11.210 ;
        RECT 137.190 10.220 138.190 10.450 ;
        RECT 127.230 9.780 129.440 9.910 ;
        RECT 127.230 9.770 129.430 9.780 ;
        RECT 127.230 9.760 127.460 9.770 ;
        RECT 137.250 9.480 138.140 10.220 ;
        RECT 137.130 9.260 138.140 9.480 ;
        RECT 110.240 8.950 111.520 9.020 ;
        RECT 45.480 7.650 46.600 8.310 ;
        RECT 43.770 6.900 46.600 7.650 ;
        RECT 43.770 6.890 52.280 6.900 ;
        RECT 58.230 6.890 59.350 8.390 ;
        RECT 71.240 6.890 72.360 8.460 ;
        RECT 84.050 8.390 85.240 8.620 ;
        RECT 97.170 8.570 98.400 8.900 ;
        RECT 110.070 8.850 111.520 8.950 ;
        RECT 123.980 8.980 126.590 9.240 ;
        RECT 137.070 9.240 138.350 9.260 ;
        RECT 139.410 9.240 139.680 10.700 ;
        RECT 140.030 10.560 140.260 10.700 ;
        RECT 140.260 10.150 140.570 10.420 ;
        RECT 140.320 9.910 140.550 10.150 ;
        RECT 142.220 9.910 142.530 10.880 ;
        RECT 140.320 9.780 142.530 9.910 ;
        RECT 140.320 9.770 142.520 9.780 ;
        RECT 140.320 9.760 140.550 9.770 ;
        RECT 137.070 8.980 139.680 9.240 ;
        RECT 123.980 8.910 125.260 8.980 ;
        RECT 137.070 8.910 138.350 8.980 ;
        RECT 84.100 6.890 85.220 8.390 ;
        RECT 97.170 8.340 98.360 8.570 ;
        RECT 110.070 8.520 111.300 8.850 ;
        RECT 123.810 8.810 125.260 8.910 ;
        RECT 136.900 8.810 138.350 8.910 ;
        RECT 97.230 6.890 98.350 8.340 ;
        RECT 110.070 8.290 111.260 8.520 ;
        RECT 123.810 8.480 125.040 8.810 ;
        RECT 110.100 6.890 111.220 8.290 ;
        RECT 123.810 8.250 125.000 8.480 ;
        RECT 136.900 8.250 138.130 8.810 ;
        RECT 43.770 6.850 112.060 6.890 ;
        RECT 123.880 6.850 125.000 8.250 ;
        RECT 137.160 6.850 138.130 8.250 ;
        RECT 43.770 6.480 141.120 6.850 ;
        RECT 45.470 6.470 141.120 6.480 ;
        RECT 51.220 6.440 141.120 6.470 ;
        RECT 110.110 6.400 141.120 6.440 ;
      LAYER met2 ;
        RECT 57.365 60.355 57.915 60.365 ;
        RECT 57.365 60.345 58.065 60.355 ;
        RECT 57.365 60.015 77.045 60.345 ;
        RECT 57.365 59.795 58.065 60.015 ;
        RECT 56.855 59.775 58.065 59.795 ;
        RECT 56.845 59.185 58.065 59.775 ;
        RECT 55.985 58.275 56.425 58.655 ;
        RECT 56.845 55.560 57.175 59.185 ;
        RECT 57.365 59.165 58.065 59.185 ;
        RECT 58.515 59.815 59.445 59.855 ;
        RECT 58.515 59.075 59.455 59.815 ;
        RECT 61.805 59.765 67.585 60.015 ;
        RECT 70.545 59.785 76.325 60.015 ;
        RECT 60.825 59.285 68.245 59.765 ;
        RECT 70.035 59.305 77.455 59.785 ;
        RECT 58.515 59.045 59.445 59.075 ;
        RECT 79.420 58.055 81.275 58.805 ;
        RECT 58.685 55.965 67.555 56.425 ;
        RECT 60.545 55.560 65.055 55.965 ;
        RECT 70.065 55.885 78.935 56.345 ;
        RECT 70.905 55.560 75.415 55.885 ;
        RECT 56.845 55.230 75.430 55.560 ;
        RECT 57.175 55.065 57.725 55.075 ;
        RECT 57.175 55.055 57.875 55.065 ;
        RECT 57.175 54.725 76.855 55.055 ;
        RECT 57.175 54.505 57.875 54.725 ;
        RECT 56.665 54.485 57.875 54.505 ;
        RECT 56.655 53.895 57.875 54.485 ;
        RECT 56.655 50.270 56.985 53.895 ;
        RECT 57.175 53.875 57.875 53.895 ;
        RECT 58.305 53.845 59.275 54.575 ;
        RECT 61.615 54.475 67.395 54.725 ;
        RECT 70.355 54.495 76.135 54.725 ;
        RECT 60.635 53.995 68.055 54.475 ;
        RECT 69.845 54.015 77.265 54.495 ;
        RECT 58.345 53.775 59.245 53.845 ;
        RECT 58.465 52.855 59.145 53.515 ;
        RECT 80.525 53.470 81.275 58.055 ;
        RECT 79.230 52.720 81.275 53.470 ;
        RECT 58.495 50.675 67.365 51.135 ;
        RECT 60.355 50.270 64.865 50.675 ;
        RECT 69.875 50.595 78.745 51.055 ;
        RECT 70.715 50.270 75.225 50.595 ;
        RECT 56.655 49.940 75.240 50.270 ;
        RECT 59.605 48.475 61.295 48.505 ;
        RECT 70.345 48.495 72.035 48.525 ;
        RECT 80.525 48.495 81.275 52.720 ;
        RECT 81.670 50.470 82.420 61.360 ;
        RECT 81.640 49.720 82.450 50.470 ;
        RECT 64.995 48.475 66.685 48.485 ;
        RECT 58.405 48.135 59.185 48.255 ;
        RECT 59.485 48.135 61.425 48.475 ;
        RECT 53.650 48.035 61.425 48.135 ;
        RECT 63.735 48.035 64.515 48.215 ;
        RECT 64.825 48.035 66.765 48.475 ;
        RECT 69.075 48.035 69.855 48.245 ;
        RECT 70.195 48.035 72.135 48.495 ;
        RECT 74.335 48.465 82.875 48.495 ;
        RECT 91.915 48.485 93.605 48.515 ;
        RECT 86.565 48.465 88.255 48.475 ;
        RECT 74.335 48.255 82.995 48.465 ;
        RECT 74.325 48.035 82.995 48.255 ;
        RECT 53.650 48.025 82.995 48.035 ;
        RECT 85.305 48.025 86.085 48.205 ;
        RECT 86.395 48.025 88.335 48.465 ;
        RECT 90.645 48.025 91.425 48.235 ;
        RECT 91.765 48.025 93.705 48.485 ;
        RECT 97.095 48.465 98.785 48.475 ;
        RECT 96.665 48.245 98.985 48.465 ;
        RECT 95.895 48.025 98.985 48.245 ;
        RECT 53.650 48.015 98.985 48.025 ;
        RECT 53.650 47.565 96.825 48.015 ;
        RECT 53.650 47.285 75.255 47.565 ;
        RECT 53.650 47.255 75.245 47.285 ;
        RECT 79.825 47.275 96.825 47.565 ;
        RECT 79.825 47.245 96.815 47.275 ;
        RECT 56.815 44.395 57.145 45.115 ;
        RECT 57.375 44.395 57.855 45.525 ;
        RECT 56.815 38.615 57.855 44.395 ;
        RECT 56.815 35.655 57.145 38.615 ;
        RECT 57.375 38.105 57.855 38.615 ;
        RECT 60.815 43.485 61.275 47.005 ;
        RECT 62.165 44.385 62.495 45.105 ;
        RECT 62.725 44.385 63.205 45.515 ;
        RECT 61.600 43.485 61.930 43.500 ;
        RECT 60.815 38.975 61.930 43.485 ;
        RECT 60.815 38.135 61.275 38.975 ;
        RECT 57.395 35.655 57.875 36.315 ;
        RECT 48.400 31.600 49.710 32.630 ;
        RECT 46.980 30.015 47.310 30.035 ;
        RECT 46.955 29.635 56.440 30.015 ;
        RECT 56.815 29.875 57.875 35.655 ;
        RECT 46.980 29.615 47.310 29.635 ;
        RECT 47.415 28.935 48.605 28.975 ;
        RECT 50.995 28.935 51.315 28.990 ;
        RECT 52.990 28.935 56.610 28.965 ;
        RECT 47.415 28.785 56.610 28.935 ;
        RECT 47.415 28.705 48.605 28.785 ;
        RECT 50.995 28.730 51.315 28.785 ;
        RECT 52.990 28.755 56.610 28.785 ;
        RECT 43.905 22.305 44.335 28.525 ;
        RECT 47.585 27.985 50.205 28.155 ;
        RECT 52.055 27.025 52.485 28.595 ;
        RECT 46.595 26.555 52.505 26.855 ;
        RECT 46.595 26.545 47.045 26.555 ;
        RECT 47.885 26.335 48.205 26.340 ;
        RECT 45.465 26.265 48.205 26.335 ;
        RECT 45.405 26.085 48.205 26.265 ;
        RECT 45.405 25.925 45.845 26.085 ;
        RECT 47.885 26.080 48.205 26.085 ;
        RECT 49.955 25.875 50.755 25.915 ;
        RECT 52.640 25.875 56.110 25.915 ;
        RECT 49.955 25.725 56.110 25.875 ;
        RECT 49.955 25.635 50.755 25.725 ;
        RECT 52.640 25.680 56.110 25.725 ;
        RECT 47.175 25.480 47.495 25.545 ;
        RECT 50.915 25.480 51.235 25.535 ;
        RECT 52.685 25.480 55.665 25.505 ;
        RECT 47.175 25.330 55.665 25.480 ;
        RECT 47.175 25.285 47.495 25.330 ;
        RECT 50.915 25.275 51.235 25.330 ;
        RECT 52.685 25.300 55.665 25.330 ;
        RECT 44.695 24.875 45.265 24.905 ;
        RECT 44.695 24.845 45.825 24.875 ;
        RECT 47.305 24.845 47.685 24.885 ;
        RECT 44.695 24.725 47.685 24.845 ;
        RECT 44.915 24.595 47.685 24.725 ;
        RECT 44.915 24.575 45.825 24.595 ;
        RECT 47.305 24.565 47.685 24.595 ;
        RECT 46.605 21.995 47.035 24.435 ;
        RECT 49.345 23.415 49.775 25.045 ;
        RECT 49.965 24.485 50.755 24.545 ;
        RECT 52.675 24.485 55.245 24.520 ;
        RECT 49.965 24.335 55.245 24.485 ;
        RECT 49.965 24.285 50.755 24.335 ;
        RECT 52.675 24.300 55.245 24.335 ;
        RECT 47.345 23.165 47.665 23.185 ;
        RECT 47.345 23.140 51.295 23.165 ;
        RECT 52.675 23.140 54.655 23.175 ;
        RECT 47.345 22.970 54.655 23.140 ;
        RECT 47.345 22.945 51.295 22.970 ;
        RECT 47.345 22.925 47.665 22.945 ;
        RECT 50.895 22.835 51.295 22.945 ;
        RECT 52.675 22.930 54.655 22.970 ;
        RECT 50.065 22.635 50.775 22.695 ;
        RECT 52.745 22.635 54.195 22.680 ;
        RECT 50.065 22.485 54.195 22.635 ;
        RECT 50.065 22.405 50.775 22.485 ;
        RECT 52.745 22.440 54.195 22.485 ;
        RECT 43.845 21.785 44.325 21.815 ;
        RECT 43.845 21.485 49.755 21.785 ;
        RECT 50.055 21.710 50.375 21.735 ;
        RECT 50.915 21.710 51.235 21.735 ;
        RECT 50.055 21.685 51.235 21.710 ;
        RECT 52.615 21.685 53.655 21.745 ;
        RECT 50.055 21.520 53.655 21.685 ;
        RECT 50.055 21.500 51.235 21.520 ;
        RECT 43.845 21.465 44.325 21.485 ;
        RECT 50.055 21.475 50.375 21.500 ;
        RECT 50.915 21.475 51.235 21.500 ;
        RECT 52.615 21.465 53.655 21.520 ;
        RECT 44.830 20.525 45.400 20.945 ;
        RECT 44.690 20.475 45.400 20.525 ;
        RECT 44.520 20.155 45.400 20.475 ;
        RECT 44.690 20.105 45.400 20.155 ;
        RECT 44.830 20.030 45.400 20.105 ;
        RECT 46.615 20.085 47.045 21.255 ;
        RECT 50.935 21.225 51.795 21.245 ;
        RECT 52.670 21.225 53.005 21.310 ;
        RECT 50.935 21.060 53.025 21.225 ;
        RECT 50.935 20.935 51.795 21.060 ;
        RECT 47.285 20.135 50.375 20.395 ;
        RECT 47.285 20.055 48.265 20.135 ;
        RECT 43.885 19.855 44.385 19.905 ;
        RECT 48.975 19.855 49.815 19.895 ;
        RECT 43.885 19.555 49.815 19.855 ;
        RECT 48.975 19.495 49.815 19.555 ;
        RECT 52.055 19.255 52.485 20.825 ;
        RECT 52.670 19.055 53.005 21.060 ;
        RECT 53.375 19.595 53.655 21.465 ;
        RECT 53.955 20.175 54.195 22.440 ;
        RECT 54.410 20.700 54.655 22.930 ;
        RECT 55.025 21.335 55.245 24.300 ;
        RECT 55.460 21.940 55.665 25.300 ;
        RECT 55.875 22.695 56.110 25.680 ;
        RECT 56.400 23.270 56.610 28.755 ;
        RECT 56.815 26.135 57.145 29.875 ;
        RECT 57.395 28.895 57.875 29.875 ;
        RECT 60.735 33.125 61.195 35.625 ;
        RECT 61.600 33.125 61.930 38.975 ;
        RECT 60.735 28.615 61.930 33.125 ;
        RECT 57.295 26.725 57.765 27.275 ;
        RECT 58.435 26.845 58.995 27.395 ;
        RECT 60.735 26.755 61.195 28.615 ;
        RECT 56.805 25.985 57.995 26.135 ;
        RECT 56.795 25.435 57.995 25.985 ;
        RECT 57.365 25.245 57.975 25.435 ;
        RECT 61.600 25.245 61.930 28.615 ;
        RECT 62.165 38.605 63.205 44.385 ;
        RECT 62.165 35.645 62.495 38.605 ;
        RECT 62.725 38.095 63.205 38.605 ;
        RECT 66.165 43.475 66.625 46.995 ;
        RECT 67.515 44.415 67.845 45.135 ;
        RECT 68.075 44.415 68.555 45.545 ;
        RECT 66.950 43.475 67.280 43.490 ;
        RECT 66.165 38.965 67.280 43.475 ;
        RECT 66.165 38.125 66.625 38.965 ;
        RECT 62.745 35.645 63.225 36.305 ;
        RECT 62.165 29.865 63.225 35.645 ;
        RECT 62.165 26.125 62.495 29.865 ;
        RECT 62.745 28.885 63.225 29.865 ;
        RECT 66.085 33.115 66.545 35.615 ;
        RECT 66.950 33.115 67.280 38.965 ;
        RECT 66.085 28.605 67.280 33.115 ;
        RECT 62.675 26.745 63.145 27.295 ;
        RECT 63.825 26.705 64.295 27.295 ;
        RECT 66.085 26.745 66.545 28.605 ;
        RECT 62.155 25.975 63.345 26.125 ;
        RECT 62.145 25.425 63.345 25.975 ;
        RECT 57.365 24.925 61.930 25.245 ;
        RECT 57.385 24.915 61.930 24.925 ;
        RECT 62.715 25.235 63.325 25.425 ;
        RECT 66.950 25.235 67.280 28.605 ;
        RECT 67.515 38.635 68.555 44.415 ;
        RECT 67.515 35.675 67.845 38.635 ;
        RECT 68.075 38.125 68.555 38.635 ;
        RECT 71.515 43.505 71.975 47.025 ;
        RECT 72.795 44.375 73.125 45.095 ;
        RECT 73.355 44.375 73.835 45.505 ;
        RECT 72.300 43.505 72.630 43.520 ;
        RECT 71.515 38.995 72.630 43.505 ;
        RECT 71.515 38.155 71.975 38.995 ;
        RECT 68.095 35.675 68.575 36.335 ;
        RECT 67.515 29.895 68.575 35.675 ;
        RECT 67.515 26.155 67.845 29.895 ;
        RECT 68.095 28.915 68.575 29.895 ;
        RECT 71.435 33.145 71.895 35.645 ;
        RECT 72.300 33.145 72.630 38.995 ;
        RECT 71.435 28.635 72.630 33.145 ;
        RECT 68.035 26.775 68.505 27.325 ;
        RECT 69.145 26.745 69.665 27.335 ;
        RECT 71.435 26.775 71.895 28.635 ;
        RECT 67.505 26.005 68.695 26.155 ;
        RECT 67.495 25.455 68.695 26.005 ;
        RECT 62.715 24.915 67.280 25.235 ;
        RECT 68.065 25.265 68.675 25.455 ;
        RECT 72.300 25.265 72.630 28.635 ;
        RECT 72.795 38.595 73.835 44.375 ;
        RECT 72.795 35.635 73.125 38.595 ;
        RECT 73.355 38.085 73.835 38.595 ;
        RECT 76.795 43.465 77.255 46.985 ;
        RECT 78.385 44.385 78.715 45.105 ;
        RECT 78.945 44.385 79.425 45.515 ;
        RECT 77.580 43.465 77.910 43.480 ;
        RECT 76.795 38.955 77.910 43.465 ;
        RECT 76.795 38.115 77.255 38.955 ;
        RECT 73.375 35.635 73.855 36.295 ;
        RECT 72.795 29.855 73.855 35.635 ;
        RECT 72.795 26.115 73.125 29.855 ;
        RECT 73.375 28.875 73.855 29.855 ;
        RECT 76.715 33.105 77.175 35.605 ;
        RECT 77.580 33.105 77.910 38.955 ;
        RECT 76.715 28.595 77.910 33.105 ;
        RECT 73.395 26.745 73.865 27.295 ;
        RECT 74.335 26.605 75.025 27.535 ;
        RECT 76.715 26.735 77.175 28.595 ;
        RECT 72.785 25.965 73.975 26.115 ;
        RECT 72.775 25.415 73.975 25.965 ;
        RECT 68.065 24.945 72.630 25.265 ;
        RECT 68.085 24.935 72.630 24.945 ;
        RECT 73.345 25.225 73.955 25.415 ;
        RECT 77.580 25.225 77.910 28.595 ;
        RECT 78.385 38.605 79.425 44.385 ;
        RECT 78.385 35.645 78.715 38.605 ;
        RECT 78.945 38.095 79.425 38.605 ;
        RECT 82.385 43.475 82.845 46.995 ;
        RECT 83.735 44.375 84.065 45.095 ;
        RECT 84.295 44.375 84.775 45.505 ;
        RECT 83.170 43.475 83.500 43.490 ;
        RECT 82.385 38.965 83.500 43.475 ;
        RECT 82.385 38.125 82.845 38.965 ;
        RECT 78.965 35.645 79.445 36.305 ;
        RECT 78.385 29.865 79.445 35.645 ;
        RECT 78.385 26.125 78.715 29.865 ;
        RECT 78.965 28.885 79.445 29.865 ;
        RECT 82.305 33.115 82.765 35.615 ;
        RECT 83.170 33.115 83.500 38.965 ;
        RECT 82.305 28.605 83.500 33.115 ;
        RECT 78.865 26.715 79.335 27.265 ;
        RECT 80.005 26.835 80.565 27.385 ;
        RECT 82.305 26.745 82.765 28.605 ;
        RECT 78.375 25.975 79.565 26.125 ;
        RECT 78.365 25.425 79.565 25.975 ;
        RECT 62.735 24.905 67.280 24.915 ;
        RECT 73.345 24.905 77.910 25.225 ;
        RECT 78.935 25.235 79.545 25.425 ;
        RECT 83.170 25.235 83.500 28.605 ;
        RECT 83.735 38.595 84.775 44.375 ;
        RECT 83.735 35.635 84.065 38.595 ;
        RECT 84.295 38.085 84.775 38.595 ;
        RECT 87.735 43.465 88.195 46.985 ;
        RECT 89.085 44.405 89.415 45.125 ;
        RECT 89.645 44.405 90.125 45.535 ;
        RECT 88.520 43.465 88.850 43.480 ;
        RECT 87.735 38.955 88.850 43.465 ;
        RECT 87.735 38.115 88.195 38.955 ;
        RECT 84.315 35.635 84.795 36.295 ;
        RECT 83.735 29.855 84.795 35.635 ;
        RECT 83.735 26.115 84.065 29.855 ;
        RECT 84.315 28.875 84.795 29.855 ;
        RECT 87.655 33.105 88.115 35.605 ;
        RECT 88.520 33.105 88.850 38.955 ;
        RECT 87.655 28.595 88.850 33.105 ;
        RECT 84.245 26.735 84.715 27.285 ;
        RECT 85.395 26.695 85.865 27.285 ;
        RECT 87.655 26.735 88.115 28.595 ;
        RECT 83.725 25.965 84.915 26.115 ;
        RECT 83.715 25.415 84.915 25.965 ;
        RECT 78.935 24.915 83.500 25.235 ;
        RECT 78.955 24.905 83.500 24.915 ;
        RECT 84.285 25.225 84.895 25.415 ;
        RECT 88.520 25.225 88.850 28.595 ;
        RECT 89.085 38.625 90.125 44.405 ;
        RECT 89.085 35.665 89.415 38.625 ;
        RECT 89.645 38.115 90.125 38.625 ;
        RECT 93.085 43.495 93.545 47.015 ;
        RECT 94.365 44.365 94.695 45.085 ;
        RECT 94.925 44.365 95.405 45.495 ;
        RECT 93.870 43.495 94.200 43.510 ;
        RECT 93.085 38.985 94.200 43.495 ;
        RECT 93.085 38.145 93.545 38.985 ;
        RECT 89.665 35.665 90.145 36.325 ;
        RECT 89.085 29.885 90.145 35.665 ;
        RECT 89.085 26.145 89.415 29.885 ;
        RECT 89.665 28.905 90.145 29.885 ;
        RECT 93.005 33.135 93.465 35.635 ;
        RECT 93.870 33.135 94.200 38.985 ;
        RECT 93.005 28.625 94.200 33.135 ;
        RECT 89.605 26.765 90.075 27.315 ;
        RECT 90.715 26.735 91.235 27.325 ;
        RECT 93.005 26.765 93.465 28.625 ;
        RECT 89.075 25.995 90.265 26.145 ;
        RECT 89.065 25.445 90.265 25.995 ;
        RECT 84.285 24.905 88.850 25.225 ;
        RECT 89.635 25.255 90.245 25.445 ;
        RECT 93.870 25.255 94.200 28.625 ;
        RECT 94.365 38.585 95.405 44.365 ;
        RECT 94.365 35.625 94.695 38.585 ;
        RECT 94.925 38.075 95.405 38.585 ;
        RECT 98.365 43.455 98.825 46.975 ;
        RECT 99.150 43.455 99.480 43.470 ;
        RECT 98.365 38.945 99.480 43.455 ;
        RECT 98.365 38.105 98.825 38.945 ;
        RECT 94.945 35.625 95.425 36.285 ;
        RECT 94.365 29.845 95.425 35.625 ;
        RECT 94.365 26.105 94.695 29.845 ;
        RECT 94.945 28.865 95.425 29.845 ;
        RECT 98.285 33.095 98.745 35.595 ;
        RECT 99.150 33.095 99.480 38.945 ;
        RECT 98.285 28.585 99.480 33.095 ;
        RECT 94.965 26.735 95.435 27.285 ;
        RECT 95.905 26.595 96.595 27.525 ;
        RECT 98.285 26.725 98.745 28.585 ;
        RECT 94.355 25.955 95.545 26.105 ;
        RECT 94.345 25.405 95.545 25.955 ;
        RECT 89.635 24.935 94.200 25.255 ;
        RECT 89.655 24.925 94.200 24.935 ;
        RECT 94.915 25.215 95.525 25.405 ;
        RECT 99.150 25.215 99.480 28.585 ;
        RECT 73.365 24.895 77.910 24.905 ;
        RECT 84.305 24.895 88.850 24.905 ;
        RECT 94.915 24.895 99.480 25.215 ;
        RECT 94.935 24.885 99.480 24.895 ;
        RECT 58.475 24.145 59.035 24.695 ;
        RECT 61.205 24.165 61.905 24.715 ;
        RECT 58.720 23.270 58.930 24.145 ;
        RECT 63.835 24.115 64.305 24.705 ;
        RECT 69.145 24.125 69.665 24.715 ;
        RECT 74.385 23.985 74.855 24.635 ;
        RECT 80.045 24.135 80.605 24.685 ;
        RECT 80.280 23.270 80.490 24.135 ;
        RECT 81.205 23.895 81.905 24.655 ;
        RECT 82.775 24.155 83.475 24.705 ;
        RECT 85.405 24.655 85.875 24.695 ;
        RECT 85.405 24.450 85.925 24.655 ;
        RECT 85.405 24.105 85.875 24.450 ;
        RECT 56.400 23.060 80.490 23.270 ;
        RECT 55.865 22.665 56.950 22.695 ;
        RECT 59.855 22.665 60.175 22.675 ;
        RECT 81.365 22.665 81.600 23.895 ;
        RECT 55.865 22.445 81.600 22.665 ;
        RECT 56.595 22.430 81.600 22.445 ;
        RECT 59.855 22.415 60.175 22.430 ;
        RECT 63.925 21.950 64.245 21.975 ;
        RECT 85.550 21.950 85.755 24.105 ;
        RECT 86.505 23.925 87.205 24.685 ;
        RECT 90.715 24.115 91.235 24.705 ;
        RECT 91.825 24.685 92.215 24.715 ;
        RECT 56.595 21.940 85.755 21.950 ;
        RECT 55.460 21.745 85.755 21.940 ;
        RECT 55.460 21.735 57.185 21.745 ;
        RECT 63.925 21.715 64.245 21.745 ;
        RECT 65.145 21.355 65.465 21.375 ;
        RECT 86.765 21.355 86.985 23.925 ;
        RECT 56.595 21.335 86.985 21.355 ;
        RECT 55.025 21.135 86.985 21.335 ;
        RECT 55.025 21.115 56.975 21.135 ;
        RECT 65.145 21.115 65.465 21.135 ;
        RECT 69.165 20.700 69.485 20.705 ;
        RECT 90.770 20.700 91.015 24.115 ;
        RECT 91.715 23.925 92.415 24.685 ;
        RECT 95.975 24.625 96.255 24.705 ;
        RECT 95.955 23.975 96.425 24.625 ;
        RECT 97.065 24.615 97.400 24.660 ;
        RECT 54.410 20.455 91.015 20.700 ;
        RECT 69.165 20.445 69.485 20.455 ;
        RECT 70.325 20.175 70.645 20.185 ;
        RECT 91.825 20.175 92.065 23.925 ;
        RECT 53.955 19.935 92.065 20.175 ;
        RECT 70.325 19.925 70.645 19.935 ;
        RECT 95.975 19.595 96.255 23.975 ;
        RECT 96.875 23.855 97.575 24.615 ;
        RECT 53.375 19.315 96.255 19.595 ;
        RECT 97.065 19.055 97.400 23.855 ;
        RECT 137.920 21.780 139.470 22.970 ;
        RECT 124.840 20.730 126.190 21.650 ;
        RECT 46.675 19.015 52.485 19.025 ;
        RECT 46.625 18.725 52.485 19.015 ;
        RECT 52.670 18.720 97.400 19.055 ;
        RECT 98.660 18.880 99.620 19.490 ;
        RECT 111.300 19.350 112.610 20.370 ;
        RECT 62.400 16.980 63.350 17.890 ;
        RECT 67.580 17.660 68.640 18.250 ;
        RECT 85.390 17.740 86.470 18.510 ;
        RECT 59.630 12.790 60.680 13.800 ;
        RECT 72.510 12.970 73.750 14.030 ;
        RECT 85.530 13.010 86.610 13.890 ;
        RECT 98.670 12.770 99.910 13.710 ;
        RECT 111.520 12.710 112.650 13.600 ;
        RECT 125.160 12.640 126.390 13.690 ;
        RECT 138.230 12.700 139.450 13.720 ;
        RECT 50.950 11.700 51.460 12.170 ;
        RECT 63.800 11.720 64.310 12.190 ;
        RECT 76.810 11.790 77.320 12.260 ;
        RECT 76.810 11.720 77.310 11.790 ;
        RECT 89.660 11.720 90.170 12.190 ;
        RECT 50.950 11.630 51.450 11.700 ;
        RECT 63.800 11.650 64.300 11.720 ;
        RECT 89.660 11.650 90.160 11.720 ;
        RECT 102.780 11.670 103.290 12.140 ;
        RECT 102.780 11.600 103.280 11.670 ;
        RECT 115.680 11.620 116.190 12.090 ;
        RECT 115.680 11.550 116.180 11.620 ;
        RECT 129.420 11.580 129.930 12.050 ;
        RECT 142.510 11.580 143.020 12.050 ;
        RECT 129.420 11.510 129.920 11.580 ;
        RECT 142.510 11.510 143.010 11.580 ;
        RECT 45.390 8.320 46.480 9.080 ;
        RECT 58.240 8.340 59.330 9.100 ;
        RECT 71.250 8.410 72.340 9.170 ;
        RECT 84.100 8.340 85.190 9.100 ;
        RECT 97.220 8.290 98.310 9.050 ;
        RECT 110.120 8.240 111.210 9.000 ;
        RECT 123.860 8.200 124.950 8.960 ;
        RECT 136.950 8.200 138.040 8.960 ;
      LAYER met3 ;
        RECT 58.465 59.760 59.495 59.830 ;
        RECT 61.185 59.760 62.035 59.820 ;
        RECT 58.440 59.030 62.035 59.760 ;
        RECT 53.670 47.230 54.600 48.160 ;
        RECT 48.990 32.605 49.860 32.700 ;
        RECT 48.350 31.770 49.860 32.605 ;
        RECT 48.350 31.625 49.785 31.770 ;
        RECT 53.695 31.655 54.575 47.230 ;
        RECT 45.865 29.635 47.335 30.015 ;
        RECT 43.865 18.665 44.345 28.785 ;
        RECT 45.865 27.265 46.245 29.635 ;
        RECT 44.925 26.885 46.245 27.265 ;
        RECT 44.925 20.925 45.305 26.885 ;
        RECT 44.805 20.305 45.425 20.925 ;
        RECT 46.585 18.665 47.065 28.785 ;
        RECT 49.305 18.655 49.785 31.625 ;
        RECT 56.015 30.040 56.395 58.655 ;
        RECT 58.295 54.435 59.295 54.530 ;
        RECT 61.185 54.435 62.035 59.030 ;
        RECT 58.295 53.800 62.035 54.435 ;
        RECT 58.355 53.790 62.035 53.800 ;
        RECT 58.415 52.880 59.195 53.490 ;
        RECT 55.990 29.610 56.420 30.040 ;
        RECT 52.025 19.490 52.505 28.775 ;
        RECT 61.185 28.295 62.035 53.790 ;
        RECT 57.105 27.755 73.935 28.295 ;
        RECT 57.285 27.250 57.775 27.755 ;
        RECT 58.465 27.370 58.915 27.455 ;
        RECT 57.245 26.750 57.815 27.250 ;
        RECT 58.385 26.870 59.045 27.370 ;
        RECT 58.465 24.670 58.915 26.870 ;
        RECT 61.185 25.790 62.035 27.755 ;
        RECT 62.665 27.270 63.155 27.755 ;
        RECT 63.825 27.270 64.325 27.395 ;
        RECT 68.025 27.300 68.515 27.755 ;
        RECT 69.135 27.310 69.675 27.375 ;
        RECT 62.625 26.770 63.195 27.270 ;
        RECT 63.775 26.730 64.345 27.270 ;
        RECT 67.985 26.800 68.555 27.300 ;
        RECT 68.025 26.795 68.515 26.800 ;
        RECT 69.095 26.770 69.715 27.310 ;
        RECT 73.375 27.270 73.865 27.755 ;
        RECT 78.675 27.745 95.505 28.285 ;
        RECT 74.315 27.350 74.915 27.475 ;
        RECT 73.345 26.770 73.915 27.270 ;
        RECT 61.185 24.690 62.080 25.790 ;
        RECT 58.425 24.170 59.085 24.670 ;
        RECT 61.155 24.190 62.080 24.690 ;
        RECT 63.825 24.680 64.325 26.730 ;
        RECT 69.135 24.690 69.675 26.770 ;
        RECT 74.295 26.700 74.915 27.350 ;
        RECT 78.855 27.240 79.345 27.745 ;
        RECT 80.035 27.360 80.485 27.445 ;
        RECT 78.815 26.740 79.385 27.240 ;
        RECT 79.955 26.860 80.615 27.360 ;
        RECT 61.190 23.685 62.080 24.190 ;
        RECT 63.785 24.140 64.355 24.680 ;
        RECT 69.095 24.150 69.715 24.690 ;
        RECT 69.135 24.135 69.675 24.150 ;
        RECT 74.315 24.025 74.915 26.700 ;
        RECT 80.035 24.660 80.485 26.860 ;
        RECT 82.755 24.680 83.605 27.745 ;
        RECT 84.235 27.260 84.725 27.745 ;
        RECT 85.395 27.260 85.895 27.385 ;
        RECT 89.595 27.290 90.085 27.745 ;
        RECT 90.705 27.300 91.245 27.365 ;
        RECT 84.195 26.760 84.765 27.260 ;
        RECT 85.345 26.720 85.915 27.260 ;
        RECT 89.555 26.790 90.125 27.290 ;
        RECT 89.595 26.785 90.085 26.790 ;
        RECT 90.665 26.760 91.285 27.300 ;
        RECT 94.945 27.260 95.435 27.745 ;
        RECT 95.885 27.340 96.485 27.465 ;
        RECT 94.915 26.760 95.485 27.260 ;
        RECT 79.995 24.160 80.655 24.660 ;
        RECT 82.725 24.180 83.605 24.680 ;
        RECT 85.395 24.670 85.895 26.720 ;
        RECT 90.705 24.680 91.245 26.760 ;
        RECT 95.865 26.690 96.485 27.340 ;
        RECT 74.335 24.010 74.905 24.025 ;
        RECT 82.755 23.685 83.605 24.180 ;
        RECT 85.355 24.130 85.925 24.670 ;
        RECT 90.665 24.140 91.285 24.680 ;
        RECT 90.705 24.125 91.245 24.140 ;
        RECT 95.885 24.015 96.485 26.690 ;
        RECT 95.905 24.000 96.475 24.015 ;
        RECT 61.165 22.745 83.650 23.685 ;
        RECT 51.980 18.500 52.910 19.490 ;
        RECT 61.165 18.495 62.105 22.745 ;
        RECT 137.870 21.805 139.520 22.945 ;
        RECT 124.790 21.620 126.240 21.625 ;
        RECT 124.790 20.755 126.260 21.620 ;
        RECT 111.250 20.290 112.660 20.345 ;
        RECT 98.610 19.360 99.670 19.465 ;
        RECT 111.250 19.375 112.780 20.290 ;
        RECT 98.610 18.905 99.700 19.360 ;
        RECT 85.540 18.485 86.520 18.530 ;
        RECT 62.350 17.560 63.400 17.865 ;
        RECT 67.490 17.590 68.720 18.230 ;
        RECT 85.340 17.765 86.520 18.485 ;
        RECT 59.690 17.005 63.400 17.560 ;
        RECT 59.690 16.700 63.370 17.005 ;
        RECT 67.630 16.940 73.630 17.590 ;
        RECT 59.650 16.450 63.370 16.700 ;
        RECT 59.650 13.775 60.640 16.450 ;
        RECT 72.570 14.005 73.630 16.940 ;
        RECT 59.580 12.815 60.730 13.775 ;
        RECT 72.460 12.995 73.800 14.005 ;
        RECT 85.540 13.865 86.520 17.765 ;
        RECT 85.480 13.035 86.660 13.865 ;
        RECT 98.990 13.685 99.700 18.905 ;
        RECT 72.570 12.920 73.630 12.995 ;
        RECT 98.620 12.795 99.960 13.685 ;
        RECT 111.670 13.575 112.780 19.375 ;
        RECT 125.190 13.665 126.260 20.755 ;
        RECT 138.250 13.695 139.490 21.805 ;
        RECT 111.470 13.040 112.780 13.575 ;
        RECT 111.470 12.735 112.700 13.040 ;
        RECT 125.110 12.665 126.440 13.665 ;
        RECT 138.180 12.725 139.500 13.695 ;
        RECT 40.580 10.000 44.440 12.400 ;
        RECT 50.900 11.725 51.510 12.145 ;
        RECT 53.430 10.020 57.290 12.420 ;
        RECT 63.750 11.745 64.360 12.165 ;
        RECT 66.440 10.090 70.300 12.490 ;
        RECT 76.760 11.815 77.370 12.235 ;
        RECT 79.290 10.020 83.150 12.420 ;
        RECT 89.610 11.745 90.220 12.165 ;
        RECT 92.410 9.970 96.270 12.370 ;
        RECT 102.730 11.695 103.340 12.115 ;
        RECT 105.310 9.920 109.170 12.320 ;
        RECT 115.630 11.645 116.240 12.065 ;
        RECT 119.050 9.880 122.910 12.280 ;
        RECT 129.370 11.605 129.980 12.025 ;
        RECT 132.140 9.880 136.000 12.280 ;
        RECT 142.460 11.605 143.070 12.025 ;
        RECT 45.340 8.345 46.530 9.055 ;
        RECT 48.470 7.270 52.330 9.670 ;
        RECT 58.190 8.365 59.380 9.075 ;
        RECT 61.320 7.290 65.180 9.690 ;
        RECT 71.200 8.435 72.390 9.145 ;
        RECT 74.330 7.360 78.190 9.760 ;
        RECT 84.050 8.365 85.240 9.075 ;
        RECT 87.180 7.290 91.040 9.690 ;
        RECT 97.170 8.315 98.360 9.025 ;
        RECT 100.300 7.240 104.160 9.640 ;
        RECT 110.070 8.265 111.260 8.975 ;
        RECT 113.200 7.190 117.060 9.590 ;
        RECT 123.810 8.225 125.000 8.935 ;
        RECT 126.940 7.150 130.800 9.550 ;
        RECT 136.900 8.225 138.090 8.935 ;
        RECT 140.030 7.150 143.890 9.550 ;
      LAYER met4 ;
        RECT 56.010 53.435 56.400 53.440 ;
        RECT 58.460 53.435 59.150 53.470 ;
        RECT 56.010 53.055 59.150 53.435 ;
        RECT 56.010 53.050 56.400 53.055 ;
        RECT 58.460 52.900 59.150 53.055 ;
        RECT 53.690 32.675 54.580 32.680 ;
        RECT 48.985 31.795 54.580 32.675 ;
        RECT 53.690 31.790 54.580 31.795 ;
        RECT 61.160 19.465 62.110 19.470 ;
        RECT 51.975 18.525 62.110 19.465 ;
        RECT 61.160 18.520 62.110 18.525 ;
        RECT 43.940 10.060 44.420 12.340 ;
        RECT 50.945 11.745 51.465 12.125 ;
        RECT 44.050 8.990 44.420 10.060 ;
        RECT 50.950 10.030 51.440 11.745 ;
        RECT 56.790 10.080 57.270 12.360 ;
        RECT 63.795 11.765 64.315 12.145 ;
        RECT 50.950 10.020 51.450 10.030 ;
        RECT 45.385 9.010 46.485 9.035 ;
        RECT 48.490 9.010 48.970 9.610 ;
        RECT 50.960 9.275 51.450 10.020 ;
        RECT 45.385 8.990 48.970 9.010 ;
        RECT 44.050 8.520 48.970 8.990 ;
        RECT 44.050 8.220 46.670 8.520 ;
        RECT 48.490 7.330 48.970 8.520 ;
        RECT 50.325 7.665 51.935 9.275 ;
        RECT 56.900 9.010 57.270 10.080 ;
        RECT 63.800 10.050 64.290 11.765 ;
        RECT 69.800 10.150 70.280 12.430 ;
        RECT 76.805 11.835 77.325 12.215 ;
        RECT 63.800 10.040 64.300 10.050 ;
        RECT 58.235 9.030 59.335 9.055 ;
        RECT 61.340 9.030 61.820 9.630 ;
        RECT 63.810 9.295 64.300 10.040 ;
        RECT 58.235 9.010 61.820 9.030 ;
        RECT 56.900 8.540 61.820 9.010 ;
        RECT 56.900 8.240 59.520 8.540 ;
        RECT 61.340 7.350 61.820 8.540 ;
        RECT 63.175 7.685 64.785 9.295 ;
        RECT 69.910 9.080 70.280 10.150 ;
        RECT 76.810 10.120 77.300 11.835 ;
        RECT 76.810 10.110 77.310 10.120 ;
        RECT 71.245 9.100 72.345 9.125 ;
        RECT 74.350 9.100 74.830 9.700 ;
        RECT 76.820 9.365 77.310 10.110 ;
        RECT 82.650 10.080 83.130 12.360 ;
        RECT 89.655 11.765 90.175 12.145 ;
        RECT 71.245 9.080 74.830 9.100 ;
        RECT 69.910 8.610 74.830 9.080 ;
        RECT 69.910 8.310 72.530 8.610 ;
        RECT 74.350 7.420 74.830 8.610 ;
        RECT 76.185 7.755 77.795 9.365 ;
        RECT 82.760 9.010 83.130 10.080 ;
        RECT 89.660 10.050 90.150 11.765 ;
        RECT 89.660 10.040 90.160 10.050 ;
        RECT 84.095 9.030 85.195 9.055 ;
        RECT 87.200 9.030 87.680 9.630 ;
        RECT 89.670 9.295 90.160 10.040 ;
        RECT 95.770 10.030 96.250 12.310 ;
        RECT 102.775 11.715 103.295 12.095 ;
        RECT 84.095 9.010 87.680 9.030 ;
        RECT 82.760 8.540 87.680 9.010 ;
        RECT 82.760 8.240 85.380 8.540 ;
        RECT 87.200 7.350 87.680 8.540 ;
        RECT 89.035 7.685 90.645 9.295 ;
        RECT 95.880 8.960 96.250 10.030 ;
        RECT 102.780 10.000 103.270 11.715 ;
        RECT 102.780 9.990 103.280 10.000 ;
        RECT 97.215 8.980 98.315 9.005 ;
        RECT 100.320 8.980 100.800 9.580 ;
        RECT 102.790 9.245 103.280 9.990 ;
        RECT 108.670 9.980 109.150 12.260 ;
        RECT 115.675 11.665 116.195 12.045 ;
        RECT 97.215 8.960 100.800 8.980 ;
        RECT 95.880 8.490 100.800 8.960 ;
        RECT 95.880 8.190 98.500 8.490 ;
        RECT 100.320 7.300 100.800 8.490 ;
        RECT 102.155 7.635 103.765 9.245 ;
        RECT 108.780 8.910 109.150 9.980 ;
        RECT 115.680 9.950 116.170 11.665 ;
        RECT 115.680 9.940 116.180 9.950 ;
        RECT 122.410 9.940 122.890 12.220 ;
        RECT 129.415 11.625 129.935 12.005 ;
        RECT 110.115 8.930 111.215 8.955 ;
        RECT 113.220 8.930 113.700 9.530 ;
        RECT 115.690 9.195 116.180 9.940 ;
        RECT 110.115 8.910 113.700 8.930 ;
        RECT 108.780 8.440 113.700 8.910 ;
        RECT 108.780 8.140 111.400 8.440 ;
        RECT 113.220 7.250 113.700 8.440 ;
        RECT 115.055 7.585 116.665 9.195 ;
        RECT 122.520 8.870 122.890 9.940 ;
        RECT 129.420 9.910 129.910 11.625 ;
        RECT 135.500 9.940 135.980 12.220 ;
        RECT 142.505 11.625 143.025 12.005 ;
        RECT 129.420 9.900 129.920 9.910 ;
        RECT 123.855 8.890 124.955 8.915 ;
        RECT 126.960 8.890 127.440 9.490 ;
        RECT 129.430 9.155 129.920 9.900 ;
        RECT 123.855 8.870 127.440 8.890 ;
        RECT 122.520 8.400 127.440 8.870 ;
        RECT 122.520 8.100 125.140 8.400 ;
        RECT 126.960 7.210 127.440 8.400 ;
        RECT 128.795 7.545 130.405 9.155 ;
        RECT 135.610 8.870 135.980 9.940 ;
        RECT 142.510 9.910 143.000 11.625 ;
        RECT 142.510 9.900 143.010 9.910 ;
        RECT 136.945 8.890 138.045 8.915 ;
        RECT 140.050 8.890 140.530 9.490 ;
        RECT 142.520 9.155 143.010 9.900 ;
        RECT 136.945 8.870 140.530 8.890 ;
        RECT 135.610 8.400 140.530 8.870 ;
        RECT 135.610 8.100 138.230 8.400 ;
        RECT 140.050 7.210 140.530 8.400 ;
        RECT 141.885 7.545 143.495 9.155 ;
  END
END tt_um_wakita_mux8onehot_cap
END LIBRARY

